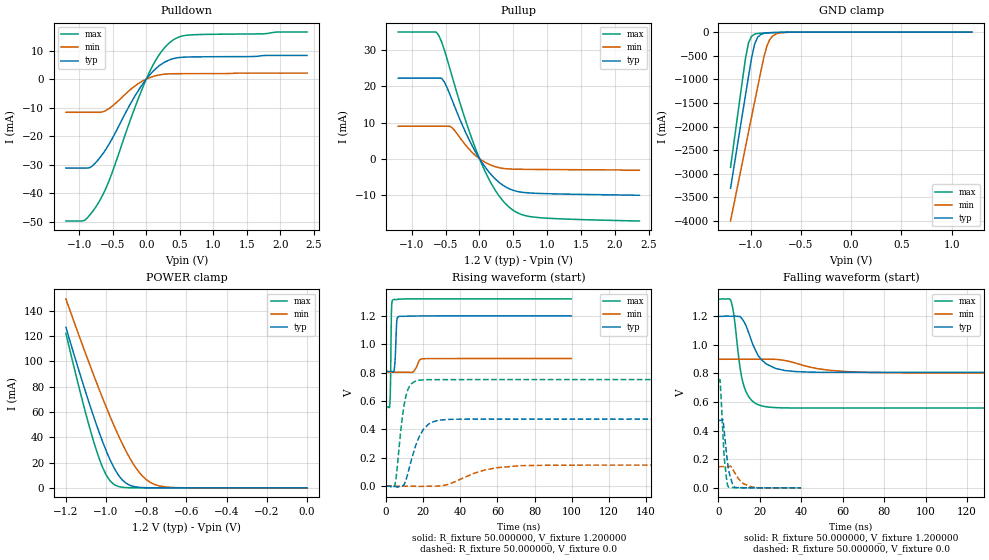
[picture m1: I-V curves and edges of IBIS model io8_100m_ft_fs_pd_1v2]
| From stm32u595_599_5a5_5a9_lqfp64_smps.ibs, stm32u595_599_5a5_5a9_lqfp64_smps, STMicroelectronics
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|   Model io8_100m_ft_fs_pd_1v2
[Model]  io8_100m_ft_fs_pd_1v2
Model_type I/O
Polarity   Non-Inverting
Enable   Active-Low
Vinl =   0.360000V
Vinh =   0.840000V
Vmeas =  0.600000V
Cref =   50.000000pF
Rref =   100.000000M
Vref =   0.0V
C_comp   2.947800pF   2.877700pF   2.996100pF
[Temperature Range]   25.000000   0.140000k   -40.000000
[Pullup Reference]   1.200000V   0.900000V   1.320000V
[Pulldown Reference]   0.0V   0.0V   0.0V
[POWER Clamp Reference]   1.200000V   0.900000V   1.320000V
[GND Clamp Reference]   0.0V   0.0V   0.0V
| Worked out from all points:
|   slope of the pulldown table from 0 to 0.18 V, typ, clamps not added: 40.7 ohm
|   slope of the pullup table from 0 to 0.18 V, typ, clamps not added: 39.5 ohm
|   GND clamp passes 1 mA (typ) near -0.51 V on its own axis
|   POWER clamp passes 1 mA (typ) near -0.86 V on its own axis
|   rising waveform, R_fixture 50.000000, V_fixture 1.200000: 20-80 % time 754ps typ, 2.06ns min, 443ps max; typ from 0.808 V to 1.2 V
|   rising waveform, R_fixture 50.000000, V_fixture 0.0: 20-80 % time 7.28ns typ, 18.3ns min, 3.99ns max; typ from 0 V to 0.472 V
|   falling waveform, R_fixture 50.000000, V_fixture 1.200000: 20-80 % time 7.88ns typ, 18.5ns min, 4.53ns max; typ from 1.2 V to 0.808 V
|   falling waveform, R_fixture 50.000000, V_fixture 0.0: 20-80 % time 2.49ns typ, 4.75ns min, 1.85ns max; typ from 0.472 V to 0 V
[Pulldown]
|Voltage   I(typ)   I(min)   I(max)
-1.2V     -31.16mA   -11.61mA   -49.71mA
-920mV    -31.16mA   -11.61mA   -49.48mA
-840mV    -31mA      -11.61mA   -47.54mA
-720mV    -28.33mA   -11.61mA   -43.58mA
-560mV    -22.95mA   -10.37mA   -35.89mA
-200mV    -7.146mA   -2.964mA   -11.89mA
0V        0A         0A         0A
160mV     4.047mA    1.298mA    7.361mA
360mV     6.87mA     1.87mA     13mA
480mV     7.543mA    1.91mA     14.69mA
640mV     7.765mA    1.923mA    15.46mA
2.4V      8.308mA    2.101mA    16.51mA
[Pullup]
|Voltage   I(typ)   I(min)   I(max)
-1.2V     22.25mA    8.971mA    35.01mA
-640mV    22.25mA    8.971mA    35.01mA
-600mV    22.25mA    8.971mA    34.03mA
-520mV    21.23mA    8.971mA    30.12mA
-400mV    15.99mA    8.489mA    22.45mA
-200mV    7.069mA    3.642mA    10.26mA
0V        0A         0A         0A
240mV     -5.73mA    -2.256mA   -8.953mA
480mV     -8.639mA   -2.877mA   -14.04mA
640mV     -9.31mA    -2.942mA   -15.55mA
880mV     -9.601mA   -2.986mA   -16.29mA
2.36V     -10.1mA    -3.2mA     -17.23mA
[GND_clamp]
|Voltage   I(typ)   I(min)   I(max)
-1.2V     -3.305A    -3.998A    -2.862A
-1.05V    -1.316A    -2.418A    -539.3mA
-1.02V    -921mA     -2.103A    -218.8mA
-990mV    -539.5mA   -1.788A    -87.45mA
-960mV    -252.2mA   -1.474A    -44.37mA
-930mV    -110.5mA   -1.16A     -30.33mA
-870mV    -28.04mA   -549.1mA   -21.1mA
-840mV    -18.44mA   -305.6mA   -18.29mA
-810mV    -13.92mA   -159.7mA   -15.75mA
-780mV    -11.24mA   -82.36mA   -13.39mA
-600mV    -2.986mA   -4.279mA   -3.072mA
1.2V      30.28uA    18.17uA    37.27uA
[POWER_clamp]
|Voltage   I(typ)   I(min)   I(max)
-1.2V     127mA      149.4mA    122.2mA
-1.12V    84.97mA    114mA      70.27mA
-1.06V    55.51mA    88.42mA    35.67mA
-1.02V    37.63mA    72.04mA    17.17mA
-1V       29.51mA    64.13mA    10.3mA
-960mV    15.69mA    48.99mA    2.571mA
-900mV    3.624mA    28.77mA    182.8uA
-840mV    490.7uA    13.24mA    11.35uA
-800mV    116.8uA    6.532mA    1.77uA
-740mV    13.2uA     1.723mA    109.1nA
-620mV    167.3nA    79.35uA    0A
0V        0A         17.84nA    0A
[Ramp]
| variable   typ   min   max
dV/dt_r  0.28341/7.27297n   88.82988m/18.29477n 0.45044/3.98024n
dV/dt_f  0.23482/7.86802n   58.05000m/18.47771n 0.45673/4.52218n
R_load = 50.000000
[Rising Waveform]
R_fixture= 50.000000
V_fixture= 1.200000
V_fixture_min= 0.900000
V_fixture_max= 1.320000
|time   V(typ)   V(min)   V(max)
0s        808mV      802.7mV    558.2mV
2.002ns   808mV      802.7mV    574.3mV
2.402ns   808.1mV    802.7mV    765.3mV
2.803ns   807.9mV    802.7mV    1.21V
3.804ns   803.9mV    802.7mV    1.313V
4.605ns   851.3mV    802.7mV    1.315V
5.806ns   1.172V     802.7mV    1.316V
6.807ns   1.195V     802.7mV    1.317V
19.62ns   1.199V     897.2mV    1.319V
99.7ns    1.199V     899.4mV    1.319V
[Rising Waveform]
R_fixture= 50.000000
V_fixture= 0.0
V_fixture_min= 0.0
V_fixture_max= 0.0
|time   V(typ)   V(min)   V(max)
0s        1.836uV    1.079uV    1.945uV
4.805ns   -2.478mV   908.2nV    12.66mV
8.408ns   -277.8uV   -126.5nV   450.6mV
10.21ns   26.56mV    1.789uV    609.2mV
12.61ns   135.9mV    47.98uV    703.9mV
17.42ns   336.6mV    -1.605mV   745.1mV
22.82ns   436mV      -111.7uV   750.3mV
34.23ns   470.2mV    16.31mV    750.6mV
72.67ns   472.3mV    144.2mV    750.7mV
299.1ns   472.4mV    148.1mV    750.7mV
[Falling Waveform]
R_fixture= 50.000000
V_fixture= 1.200000
V_fixture_min= 0.900000
V_fixture_max= 1.320000
|time   V(typ)   V(min)   V(max)
0s        1.199V     899.4mV    1.319V
6.006ns   1.2V       899.5mV    1.309V
7.608ns   1.201V     900mV      1.189V
10.41ns   1.198V     900mV      841mV
12.01ns   1.169V     899.8mV    725.5mV
15.62ns   1.043V     899.6mV    618.5mV
20.82ns   895.3mV    899.6mV    573.7mV
38.04ns   812.6mV    869.1mV    558.4mV
72.47ns   807.9mV    807.3mV    558.2mV
199.4ns   808mV      802.7mV    558.2mV
[Falling Waveform]
R_fixture= 50.000000
V_fixture= 0.0
V_fixture_min= 0.0
V_fixture_max= 0.0
|time   V(typ)   V(min)   V(max)
0s        472.4mV    148.1mV    750.7mV
800.8ps   472.4mV    148.1mV    742.4mV
2.162ns   472.9mV    148.1mV    370mV
3.043ns   356.7mV    148.1mV    172.2mV
4.084ns   213.5mV    147.9mV    42.43mV
4.725ns   141.8mV    148.4mV    7.59mV
7.928ns   3.644mV    103.3mV    955.4uV
11.61ns   1.053mV    33.9mV     280.4uV
17.38ns   292.5uV    2.83mV     68.81uV
39.88ns   1.836uV    1.079uV    1.945uV
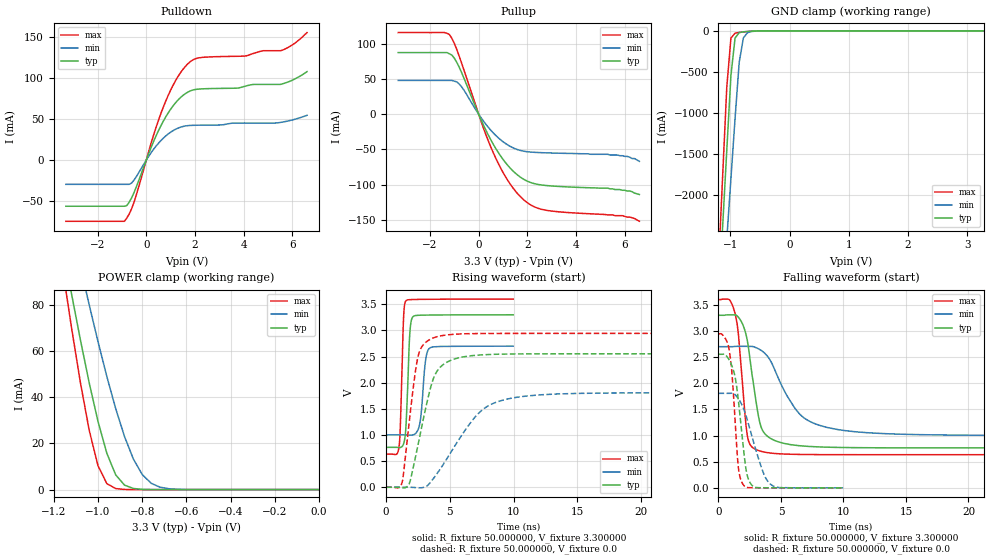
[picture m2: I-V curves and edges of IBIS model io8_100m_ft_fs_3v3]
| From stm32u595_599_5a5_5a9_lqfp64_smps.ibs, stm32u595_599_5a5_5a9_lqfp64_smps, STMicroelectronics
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|   Model io8_100m_ft_fs_3v3
[Model]  io8_100m_ft_fs_3v3
Model_type I/O
Polarity   Non-Inverting
Enable   Active-Low
Vinl =   0.990000V
Vinh =   2.310000V
Vmeas =  1.650000V
Cref =   50.000000pF
Rref =   100.000000M
Vref =   0.0V
C_comp   3.313100pF   3.281800pF   3.354500pF
[Temperature Range]   25.000000   0.140000k   -40.000000
[Pullup Reference]   3.300000V   2.700000V   3.600000V
[Pulldown Reference]   0.0V   0.0V   0.0V
[POWER Clamp Reference]   3.300000V   2.700000V   3.600000V
[GND Clamp Reference]   0.0V   0.0V   0.0V
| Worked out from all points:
|   slope of the pulldown table from 0 to 0.495 V, typ, clamps not added: 14 ohm
|   slope of the pullup table from 0 to 0.495 V, typ, clamps not added: 13.7 ohm
|   GND clamp passes 1 mA (typ) near -0.51 V on its own axis
|   POWER clamp passes 1 mA (typ) near -0.85 V on its own axis
|   rising waveform, R_fixture 50.000000, V_fixture 3.300000: 20-80 % time 245ps typ, 343ps min, 208ps max; typ from 0.764 V to 3.3 V
|   rising waveform, R_fixture 50.000000, V_fixture 0.0: 20-80 % time 1.41ns typ, 3.11ns min, 873ps max; typ from 0 V to 2.55 V
|   falling waveform, R_fixture 50.000000, V_fixture 3.300000: 20-80 % time 962ps typ, 2.52ns min, 631ps max; typ from 3.3 V to 0.764 V
|   falling waveform, R_fixture 50.000000, V_fixture 0.0: 20-80 % time 727ps typ, 1.36ns min, 504ps max; typ from 2.55 V to 0 V
[Pulldown]
|Voltage   I(typ)   I(min)   I(max)
-3.3V     -56.06mA   -29.42mA   -74.35mA
-900mV    -56.06mA   -29.42mA   -74.35mA
-700mV    -51.09mA   -29.42mA   -65.48mA
-500mV    -39.32mA   -24.2mA    -50.88mA
300mV     22.62mA    13.13mA    30.43mA
800mV     52.54mA    29.36mA    71.75mA
1.3V      72.91mA    38.82mA    101.4mA
1.8V      84.02mA    42.13mA    119.4mA
2.2V      86.43mA    42.46mA    124.5mA
5.5V      91.98mA    45.75mA    132.9mA
6.1V      98.6mA     49.6mA     142.1mA
6.6V      107.5mA    54.5mA     155mA
[Pullup]
|Voltage   I(typ)   I(min)   I(max)
-3.3V     87.21mA    47.72mA    115.6mA
-1.2V     85.52mA    47.72mA    112.9mA
-1V       79.41mA    46.66mA    100.4mA
-700mV    59.08mA    38.76mA    72.42mA
100mV     -8.009mA   -5.102mA   -10.2mA
600mV     -42.64mA   -26.6mA    -54.61mA
1.2V      -72.81mA   -43.84mA   -94.18mA
1.9V      -93.37mA   -52.9mA    -122.9mA
2.3V      -98.71mA   -54.23mA   -131.6mA
2.8V      -101.3mA   -54.97mA   -136.5mA
5.7V      -107mA     -58mA      -144mA
6.6V      -114mA     -67mA      -152mA
[GND_clamp]
|Voltage   I(typ)   I(min)   I(max)
-3.3V     -9.848A    -9.957A    -9.458A
-1.2V     -3.312A    -4.013A    -2.863A
-1.13V    -2.381A    -3.274A    -1.769A
-1.06V    -1.452A    -2.535A    -684.7mA
-990mV    -542.9mA   -1.798A    -88.02mA
-920mV    -87.11mA   -1.064A    -28.44mA
-850mV    -22.1mA    -382.4mA   -19.61mA
-780mV    -11.97mA   -86.98mA   -13.71mA
-710mV    -7.619mA   -22.26mA   -8.745mA
-640mV    -4.493mA   -7.773mA   -4.817mA
-360mV    -31.22uA   -172.6uA   -8.607uA
3.28V     0A         15.66nA    -5.841nA
[POWER_clamp]
|Voltage   I(typ)   I(min)   I(max)
-3.28V    1.355A     1.167A     1.664A
-1.16V    105.7mA    131.6mA    95.69mA
-1.12V    84.97mA    114mA      70.27mA
-1.08V    65.05mA    96.83mA    46.54mA
-1.04V    46.34mA    80.15mA    25.76mA
-1V       29.51mA    64.13mA    10.3mA
-960mV    15.69mA    48.99mA    2.571mA
-920mV    6.373mA    35.1mA     455.6uA
-840mV    490.7uA    13.24mA    11.36uA
-760mV    27.33uA    2.767mA    276.6nA
-640mV    346.6nA    134.1uA    15.62nA
0V        0A         19.91nA    0A
[Ramp]
| variable   typ   min   max
dV/dt_r  1.53252/1.41111n   1.08438/3.10153n   1.76664/0.87123n
dV/dt_f  1.52149/0.95835n   1.01892/2.51269n   1.77964/0.62530n
R_load = 50.000000
[Rising Waveform]
R_fixture= 50.000000
V_fixture= 3.300000
V_fixture_min= 2.700000
V_fixture_max= 3.600000
|time   V(typ)   V(min)   V(max)
0s        764.2mV    1.002V     633.9mV
1.021ns   760mV      1.002V     794mV
1.361ns   826.9mV    1.002V     3.216V
1.542ns   1.121V     1.002V     3.565V
1.842ns   2.884V     999.4mV    3.59V
2.102ns   3.263V     1.002V     3.592V
2.623ns   3.292V     1.198V     3.595V
3.083ns   3.294V     2.409V     3.596V
3.423ns   3.295V     2.664V     3.597V
9.97ns    3.3V       2.7V       3.6V
[Rising Waveform]
R_fixture= 50.000000
V_fixture= 0.0
V_fixture_min= 0.0
V_fixture_max= 0.0
|time   V(typ)   V(min)   V(max)
0s        8.008uV    7.157uV    6.555uV
1.201ns   -7.026mV   12.94uV    54.62mV
1.802ns   59.79mV    -885.5nV   1.225V
2.302ns   579.4mV    -6.089mV   2.227V
2.603ns   930.2mV    -10.13mV   2.59V
3.504ns   1.921V     103.9mV    2.836V
4.204ns   2.287V     335.2mV    2.893V
7.407ns   2.532V     1.452V     2.942V
10.51ns   2.551V     1.731V     2.944V
49.85ns   2.554V     1.807V     2.944V
[Falling Waveform]
R_fixture= 50.000000
V_fixture= 3.300000
V_fixture_min= 2.700000
V_fixture_max= 3.600000
|time   V(typ)   V(min)   V(max)
0s        3.3V       2.7V       3.6V
1.301ns   3.307V     2.704V     3.356V
1.602ns   3.26V      2.706V     2.919V
2.002ns   3.088V     2.706V     1.743V
2.402ns   2.676V     2.706V     898.8mV
3.103ns   1.5V       2.67V      722.6mV
3.504ns   1.108V     2.614V     693.1mV
6.507ns   805.4mV    1.408V     639.2mV
9.61ns    773.2mV    1.112V     634.7mV
49.85ns   764.2mV    1.002V     633.9mV
[Falling Waveform]
R_fixture= 50.000000
V_fixture= 0.0
V_fixture_min= 0.0
V_fixture_max= 0.0
|time   V(typ)   V(min)   V(max)
0s        2.554V     1.807V     2.944V
860.9ps   2.444V     1.807V     2.631V
1.101ns   2.315V     1.811V     2.115V
1.582ns   1.687V     1.707V     408.2mV
2.022ns   699.6mV    1.505V     46.54mV
2.282ns   257.8mV    1.317V     7.734mV
2.583ns   75.88mV    1.064V     3.106mV
3.564ns   2.516mV    303mV      1.396mV
4.184ns   1.63mV     64.39mV    1.075mV
9.97ns    8.008uV    7.157uV    6.555uV
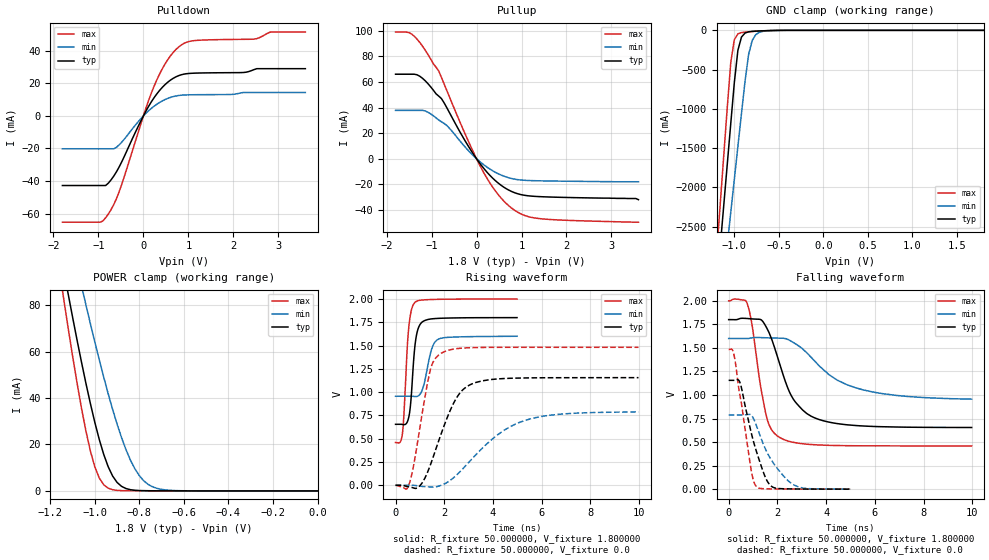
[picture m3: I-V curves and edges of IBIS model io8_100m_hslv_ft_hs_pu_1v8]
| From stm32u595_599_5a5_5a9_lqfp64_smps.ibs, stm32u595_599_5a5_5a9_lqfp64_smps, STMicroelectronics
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|   Model io8_100m_hslv_ft_hs_pu_1v8
[Model]  io8_100m_hslv_ft_hs_pu_1v8
Model_type I/O
Polarity   Non-Inverting
Enable   Active-Low
Vinl =   0.540000V
Vinh =   1.260000V
Vmeas =  0.900000V
Cref =   50.000000pF
Rref =   100.000000M
Vref =   0.0V
C_comp   3.235100pF   3.233200pF   3.282800pF
[Temperature Range]   25.000000   0.140000k   -40.000000
[Pullup Reference]   1.800000V   1.600000V   2.000000V
[Pulldown Reference]   0.0V   0.0V   0.0V
[POWER Clamp Reference]   1.800000V   1.600000V   2.000000V
[GND Clamp Reference]   0.0V   0.0V   0.0V
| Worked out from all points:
|   slope of the pulldown table from 0 to 0.27 V, typ, clamps not added: 21.7 ohm
|   slope of the pullup table from 0 to 0.27 V, typ, clamps not added: 22.6 ohm
|   GND clamp passes 1 mA (typ) near -0.51 V on its own axis
|   POWER clamp passes 1 mA (typ) near -0.86 V on its own axis
|   rising waveform, R_fixture 50.000000, V_fixture 1.800000: 20-80 % time 211ps typ, 326ps min, 197ps max; typ from 0.655 V to 1.8 V
|   rising waveform, R_fixture 50.000000, V_fixture 0.0: 20-80 % time 1.02ns typ, 2.03ns min, 582ps max; typ from 0.001 V to 1.16 V
|   falling waveform, R_fixture 50.000000, V_fixture 1.800000: 20-80 % time 1.08ns typ, 2.01ns min, 566ps max; typ from 1.8 V to 0.655 V
|   falling waveform, R_fixture 50.000000, V_fixture 0.0: 20-80 % time 711ps typ, 991ps min, 511ps max; typ from 1.16 V to 0.001 V
[Pulldown]
|Voltage   I(typ)   I(min)   I(max)
-1.8V     -42.74mA   -20.21mA   -65.25mA
-960mV    -42.74mA   -20.21mA   -65.25mA
-780mV    -41.3mA    -20.21mA   -60.25mA
-540mV    -31.39mA   -17.82mA   -46.65mA
0V        0A         0A         0A
240mV     11.28mA    6.002mA    18.38mA
480mV     19.17mA    10.02mA    31.83mA
780mV     24.67mA    12.5mA     42.21mA
1.14V     26.24mA    12.99mA    46.23mA
2.46V     28.42mA    14.38mA    47.14mA
2.82V     28.99mA    14.38mA    51.44mA
3.6V      28.99mA    14.38mA    51.44mA
[Pullup]
|Voltage   I(typ)   I(min)   I(max)
-1.8V     66.02mA    37.77mA    98.94mA
-1.44V    66.02mA    37.77mA    97.34mA
-1.14V    60.88mA    37.29mA    84.8mA
-840mV    48.91mA    30.23mA    68.54mA
-660mV    39.82mA    25.94mA    53.25mA
-300mV    16.72mA    11mA       23.08mA
120mV     -5.748mA   -3.603mA   -8.316mA
420mV     -17.18mA   -10.64mA   -25.23mA
780mV     -25.61mA   -15.48mA   -38.6mA
1.08V     -28.66mA   -16.9mA    -44.47mA
1.38V     -29.58mA   -17.26mA   -46.72mA
3.6V      -32mA      -18mA      -49.6mA
[GND_clamp]
|Voltage   I(typ)   I(min)   I(max)
-1.8V     -9.707A    -9.942A    -9.774A
-1.2V     -3.309A    -4.006A    -2.864A
-1.16V    -2.777A    -3.584A    -2.239A
-1.12V    -2.246A    -3.162A    -1.614A
-1.04V    -1.186A    -2.319A    -408.6mA
-1V       -663.9mA   -1.898A    -117.8mA
-960mV    -254mA     -1.478A    -45.14mA
-920mV    -86.03mA   -1.06A     -28.58mA
-840mV    -19.12mA   -308.9mA   -18.74mA
-800mV    -13.39mA   -130.8mA   -15.31mA
-720mV    -7.948mA   -25.37mA   -9.381mA
1.8V      0A         14.95nA    0A
[POWER_clamp]
|Voltage   I(typ)   I(min)   I(max)
-1.8V     470.9mA    433.7mA    554.6mA
-1.14V    95.28mA    122.7mA    82.88mA
-1.12V    85mA       114mA      70.34mA
-1.06V    55.55mA    88.43mA    35.73mA
-1.04V    46.38mA    80.17mA    25.83mA
-1V       29.54mA    64.14mA    10.37mA
-940mV    10.43mA    41.88mA    1.177mA
-900mV    3.66mA     28.79mA    250.5uA
-840mV    527.2uA    13.26mA    94.87uA
-800mV    153.8uA    6.55mA     88.76uA
-740mV    60.08uA    1.741mA    70.81uA
0V        0A         18.15nA    0A
[Ramp]
| variable   typ   min   max
dV/dt_r  0.69287/1.02352n   0.47044/2.02009n   0.88849/0.58120n
dV/dt_f  0.68675/1.08263n   0.37898/1.99355n   0.92438/0.56597n
R_load = 50.000000
[Rising Waveform]
R_fixture= 50.000000
V_fixture= 1.800000
V_fixture_min= 1.600000
V_fixture_max= 2.000000
|time   V(typ)   V(min)   V(max)
0s        655mV      956.1mV    459.6mV
200.2ps   655.2mV    956.2mV    468.1mV
290.3ps   653.6mV    956.3mV    573.3mV
520.5ps   708.7mV    956.7mV    1.632V
620.6ps   881.1mV    956.6mV    1.843V
780.8ps   1.46V      953.9mV    1.959V
1.031ns   1.736V     988.3mV    1.987V
1.481ns   1.787V     1.462V     1.995V
1.752ns   1.792V     1.568V     1.996V
4.985ns   1.8V       1.6V       1.999V
[Rising Waveform]
R_fixture= 50.000000
V_fixture= 0.0
V_fixture_min= 0.0
V_fixture_max= 0.0
|time   V(typ)   V(min)   V(max)
0s        502.3uV    658.3uV    580.3uV
560.6ps   -17.27mV   654uV      15.83mV
1.001ns   -3.887mV   -9.049mV   622.6mV
1.421ns   213.2mV    -17.61mV   1.232V
1.882ns   560.3mV    1.428mV    1.419V
2.563ns   962.7mV    124.8mV    1.468V
3.303ns   1.105V     330.2mV    1.479V
4.424ns   1.146V     585.6mV    1.481V
5.626ns   1.154V     719.8mV    1.482V
9.97ns    1.156V     787.5mV    1.482V
[Falling Waveform]
R_fixture= 50.000000
V_fixture= 1.800000
V_fixture_min= 1.600000
V_fixture_max= 2.000000
|time   V(typ)   V(min)   V(max)
0s        1.8V       1.6V       1.999V
740.7ps   1.812V     1.599V     1.984V
920.9ps   1.808V     1.605V     1.802V
1.301ns   1.802V     1.609V     1.106V
1.542ns   1.721V     1.607V     783.5mV
2.082ns   1.34V      1.603V     550.7mV
2.683ns   944.8mV    1.552V     496.1mV
3.704ns   740.3mV    1.313V     469.5mV
5.786ns   667.7mV    1.039V     460.5mV
9.97ns    655mV      956.1mV    459.6mV
[Falling Waveform]
R_fixture= 50.000000
V_fixture= 0.0
V_fixture_min= 0.0
V_fixture_max= 0.0
|time   V(typ)   V(min)   V(max)
0s        1.156V     787.5mV    1.482V
210.2ps   1.156V     787.6mV    1.434V
450.5ps   1.14V      787.7mV    1.012V
940.9ps   583.8mV    781.8mV    177.3mV
1.141ns   399.4mV    673.4mV    26.79mV
1.481ns   141.5mV    442.7mV    4.929mV
1.682ns   48.67mV    339.8mV    3.591mV
2.563ns   3.225mV    64.23mV    1.463mV
3.063ns   1.947mV    11.46mV    1.045mV
4.985ns   502.3uV    658.3uV    580.3uV
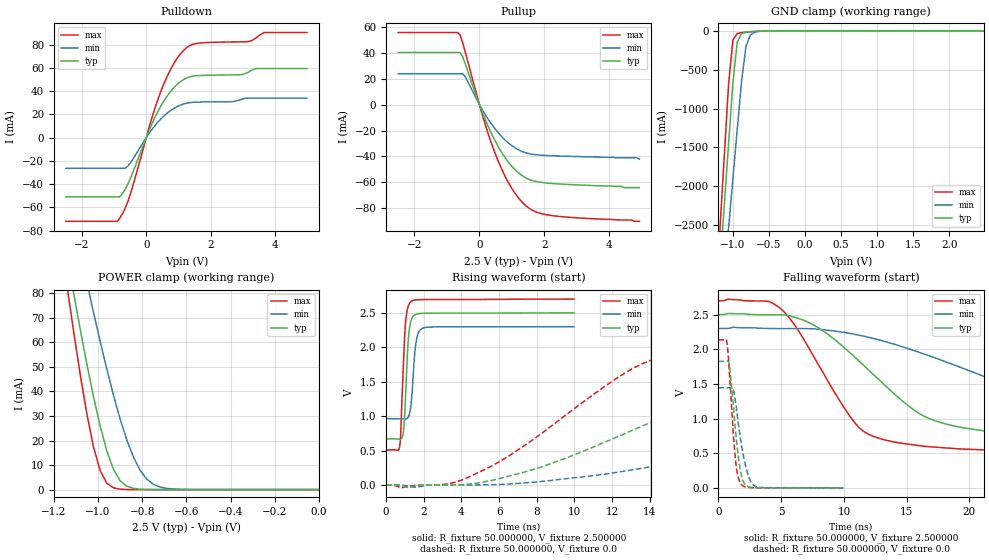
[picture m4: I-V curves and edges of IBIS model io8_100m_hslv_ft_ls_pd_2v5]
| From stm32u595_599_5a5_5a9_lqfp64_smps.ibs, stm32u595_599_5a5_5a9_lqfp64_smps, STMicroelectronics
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|   Model io8_100m_hslv_ft_ls_pd_2v5
[Model]  io8_100m_hslv_ft_ls_pd_2v5
Model_type I/O
Polarity   Non-Inverting
Enable   Active-Low
Vinl =   0.750000V
Vinh =   1.750000V
Vmeas =  1.250000V
Cref =   50.000000pF
Rref =   100.000000M
Vref =   0.0V
C_comp   3.340800pF   3.338500pF   3.380300pF
[Temperature Range]   25.000000   0.140000k   -40.000000
[Pullup Reference]   2.500000V   2.300000V   2.700000V
[Pulldown Reference]   0.0V   0.0V   0.0V
[POWER Clamp Reference]   2.500000V   2.300000V   2.700000V
[GND Clamp Reference]   0.0V   0.0V   0.0V
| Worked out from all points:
|   slope of the pulldown table from 0 to 0.375 V, typ, clamps not added: 16.1 ohm
|   slope of the pullup table from 0 to 0.375 V, typ, clamps not added: 16.6 ohm
|   GND clamp passes 1 mA (typ) near -0.50 V on its own axis
|   POWER clamp passes 1 mA (typ) near -0.86 V on its own axis
|   rising waveform, R_fixture 50.000000, V_fixture 2.500000: 20-80 % time 198ps typ, 224ps min, 202ps max; typ from 0.67 V to 2.5 V
|   rising waveform, R_fixture 50.000000, V_fixture 0.0: 20-80 % time 9.99ns typ, 18.1ns min, 6.67ns max; typ from 0 V to 1.82 V
|   falling waveform, R_fixture 50.000000, V_fixture 2.500000: 20-80 % time 7.08ns typ, 14.2ns min, 4.43ns max; typ from 2.5 V to 0.67 V
|   falling waveform, R_fixture 50.000000, V_fixture 0.0: 20-80 % time 598ps typ, 782ps min, 495ps max; typ from 1.82 V to 0 V
[Pulldown]
|Voltage   I(typ)   I(min)   I(max)
-2.5V     -51.01mA   -26.45mA   -72.04mA
-900mV    -51.01mA   -26.45mA   -72.04mA
-820mV    -50.89mA   -26.45mA   -69.09mA
-500mV    -35.59mA   -21.93mA   -49.09mA
140mV     9.489mA    5.639mA    13.76mA
460mV     27.5mA     16.24mA    40.22mA
860mV     43.07mA    25.18mA    63.88mA
1.26V     51.38mA    29.65mA    77.49mA
1.66V     53.45mA    30.63mA    81.42mA
3.18V     56.44mA    34.01mA    82.68mA
3.66V     59.44mA    34.01mA    90.42mA
5V        59.44mA    34.01mA    90.42mA
[Pullup]
|Voltage   I(typ)   I(min)   I(max)
-2.5V     40.22mA    23.82mA    55.53mA
-680mV    40.22mA    23.82mA    55.53mA
-600mV    40.22mA    23.82mA    53.98mA
-440mV    31.7mA     21.6mA     40.82mA
120mV     -7.857mA   -5.279mA   -10.51mA
520mV     -29.75mA   -19.94mA   -40.02mA
760mV     -39.83mA   -26.61mA   -53.83mA
1V        -47.69mA   -31.74mA   -64.85mA
1.48V     -57.16mA   -37.55mA   -79.04mA
1.8V      -59.59mA   -38.81mA   -83.34mA
2.28V     -60.92mA   -39.5mA    -85.75mA
4.92V     -64mA      -42mA      -90mA
[GND_clamp]
|Voltage   I(typ)   I(min)   I(max)
-2.5V     -9.446A    -9.524A    -9.146A
-1.18V    -3.045A    -3.8A      -2.552A
-1.12V    -2.248A    -3.166A    -1.614A
-1.06V    -1.452A    -2.533A    -685.4mA
-1V       -665mA     -1.901A    -117.9mA
-940mV    -148mA     -1.272A    -34.34mA
-880mV    -35.14mA   -651.5mA   -22.8mA
-820mV    -16.02mA   -203.9mA   -17.08mA
-760mV    -10.47mA   -56.89mA   -12.28mA
-700mV    -7.079mA   -18.53mA   -8.16mA
-400mV    -112.4uA   -382.5uA   -53.84uA
2.48V     63.1uA     48.03uA    77.39uA
[POWER_clamp]
|Voltage   I(typ)   I(min)   I(max)
-2.49V    881mA      773.1mA    1.07A
-1.14V    95.25mA    122.7mA    82.82mA
-1.11V    79.9mA     109.7mA    64.14mA
-1.05V    50.87mA    84.26mA    30.57mA
-1.02V    37.63mA    72.04mA    17.17mA
-990mV    25.71mA    60.25mA    7.621mA
-930mV    8.217mA    38.43mA    713.9uA
-900mV    3.624mA    28.77mA    182.8uA
-840mV    490.7uA    13.24mA    11.35uA
-780mV    56.55uA    4.324mA    699nA
-660mV    716.5nA    226uA      9.775nA
0V        0A         19.49nA    0A
[Ramp]
| variable   typ   min   max
dV/dt_r  1.09464/9.98017n   0.86544/18.06439n   1.28148/6.66219n
dV/dt_f  1.09787/7.06791n   0.80199/14.15454n   1.31323/4.42247n
R_load = 50.000000
[Rising Waveform]
R_fixture= 50.000000
V_fixture= 2.500000
V_fixture_min= 2.300000
V_fixture_max= 2.700000
|time   V(typ)   V(min)   V(max)
0s        669.5mV    962.5mV    510.5mV
720.7ps   665.8mV    962.5mV    563.1mV
780.8ps   667.4mV    962.4mV    792.1mV
920.9ps   780.8mV    961.4mV    1.768V
1.021ns   1.226V     958.8mV    2.324V
1.161ns   2.048V     980.5mV    2.586V
1.321ns   2.383V     1.168V     2.664V
1.582ns   2.477V     2.059V     2.688V
1.922ns   2.492V     2.275V     2.693V
9.97ns    2.499V     2.299V     2.699V
[Rising Waveform]
R_fixture= 50.000000
V_fixture= 0.0
V_fixture_min= 0.0
V_fixture_max= 0.0
|time   V(typ)   V(min)   V(max)
0s        2.474nV    121.9nV    2.503nV
2.803ns   -1.325mV   -1.105mV   2.414mV
4.404ns   13.92mV    35.28uV    117.6mV
8.008ns   241.7mV    44.82mV    699.7mV
14.01ns   904mV      262.5mV    1.805V
18.82ns   1.423V     502.2mV    2.033V
21.62ns   1.594V     649.8mV    2.081V
33.63ns   1.787V     1.183V     2.131V
50.45ns   1.821V     1.389V     2.136V
199.4ns   1.825V     1.442V     2.136V
[Falling Waveform]
R_fixture= 50.000000
V_fixture= 2.500000
V_fixture_min= 2.300000
V_fixture_max= 2.700000
|time   V(typ)   V(min)   V(max)
0s        2.499V     2.299V     2.699V
4.004ns   2.497V     2.299V     2.69V
5.205ns   2.496V     2.298V     2.544V
8.008ns   2.304V     2.287V     1.762V
11.61ns   1.759V     2.187V     809.5mV
16.02ns   1.071V     1.954V     608.4mV
19.22ns   876.7mV    1.743V     561.7mV
29.63ns   721.9mV    1.21V      520mV
49.25ns   676.3mV    1.018V     511mV
199.4ns   669.5mV    962.5mV    510.5mV
[Falling Waveform]
R_fixture= 50.000000
V_fixture= 0.0
V_fixture_min= 0.0
V_fixture_max= 0.0
|time   V(typ)   V(min)   V(max)
0s        1.825V     1.442V     2.136V
620.6ps   1.824V     1.443V     2.138V
840.8ps   1.796V     1.443V     1.729V
1.141ns   1.276V     1.438V     887.5mV
1.361ns   815.7mV    1.229V     394.3mV
1.562ns   476.7mV    954.7mV    160.7mV
1.822ns   179.9mV    628.8mV    51.24mV
2.362ns   18.82mV    184.6mV    6.293mV
2.943ns   2.456mV    21.58mV    1.465mV
9.97ns    2.474nV    121.9nV    2.503nV
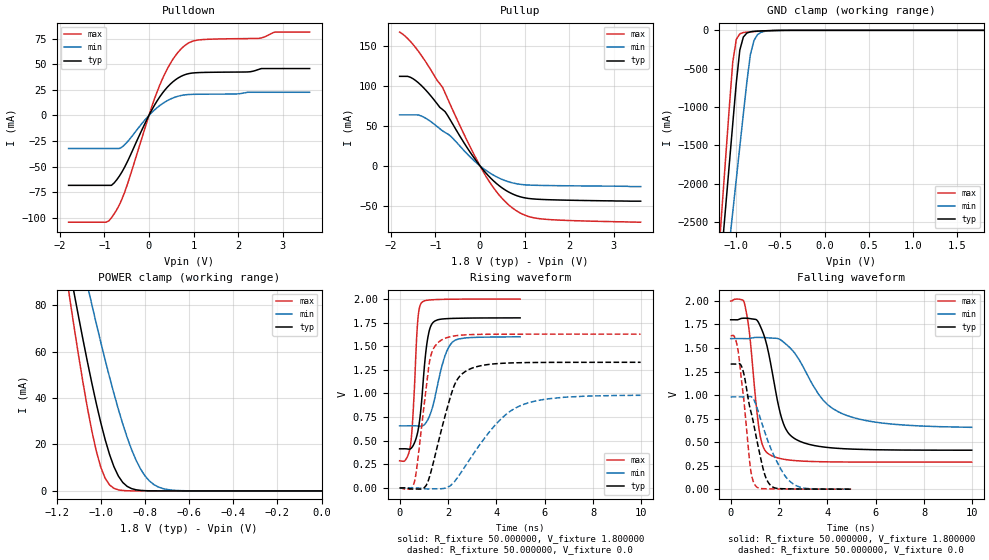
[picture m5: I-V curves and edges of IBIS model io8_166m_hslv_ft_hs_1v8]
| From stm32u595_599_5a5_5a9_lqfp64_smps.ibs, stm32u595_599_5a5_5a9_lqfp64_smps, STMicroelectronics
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|   Model io8_166m_hslv_ft_hs_1v8
[Model]  io8_166m_hslv_ft_hs_1v8
Model_type I/O
Polarity   Non-Inverting
Enable   Active-Low
Vinl =   0.540000V
Vinh =   1.260000V
Vmeas =  0.900000V
Cref =   50.000000pF
Rref =   100.000000M
Vref =   0.0V
C_comp   3.358400pF   3.352800pF   3.400400pF
[Temperature Range]   25.000000   0.140000k   -40.000000
[Pullup Reference]   1.800000V   1.600000V   2.000000V
[Pulldown Reference]   0.0V   0.0V   0.0V
[POWER Clamp Reference]   1.800000V   1.600000V   2.000000V
[GND Clamp Reference]   0.0V   0.0V   0.0V
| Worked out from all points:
|   slope of the pulldown table from 0 to 0.27 V, typ, clamps not added: 13.6 ohm
|   slope of the pullup table from 0 to 0.27 V, typ, clamps not added: 15.9 ohm
|   GND clamp passes 1 mA (typ) near -0.51 V on its own axis
|   POWER clamp passes 1 mA (typ) near -0.86 V on its own axis
|   rising waveform, R_fixture 50.000000, V_fixture 1.800000: 20-80 % time 311ps typ, 546ps min, 203ps max; typ from 0.414 V to 1.8 V
|   rising waveform, R_fixture 50.000000, V_fixture 0.0: 20-80 % time 838ps typ, 1.81ns min, 451ps max; typ from 0 V to 1.33 V
|   falling waveform, R_fixture 50.000000, V_fixture 1.800000: 20-80 % time 688ps typ, 1.56ns min, 401ps max; typ from 1.8 V to 0.414 V
|   falling waveform, R_fixture 50.000000, V_fixture 0.0: 20-80 % time 636ps typ, 926ps min, 386ps max; typ from 1.33 V to 0 V
[Pulldown]
|Voltage   I(typ)   I(min)   I(max)
-1.8V     -68.38mA   -32.32mA   -104.4mA
-960mV    -68.38mA   -32.32mA   -104.4mA
-780mV    -66.08mA   -32.32mA   -96.42mA
-540mV    -50.22mA   -28.51mA   -74.66mA
0V        0A         -400fA     10fA
240mV     18.04mA    9.6mA      29.42mA
480mV     30.68mA    16.02mA    50.95mA
780mV     39.48mA    19.99mA    67.57mA
1.14V     41.99mA    20.78mA    74.01mA
2.46V     45.09mA    22.69mA    75.45mA
2.82V     45.91mA    22.69mA    81.58mA
3.6V      45.91mA    22.69mA    81.58mA
[Pullup]
|Voltage   I(typ)   I(min)   I(max)
-1.8V     111.9mA    63.74mA    167.2mA
-1.56V    110.8mA    63.74mA    155.7mA
-1.26V    97.43mA    60.93mA    133.8mA
-840mV    70.5mA     43.75mA    98.31mA
-660mV    56.92mA    37.26mA    75.93mA
-300mV    23.77mA    15.64mA    32.82mA
120mV     -8.174mA   -5.123mA   -11.83mA
420mV     -24.43mA   -15.12mA   -35.87mA
720mV     -34.96mA   -21.23mA   -52.43mA
1.02V     -40.21mA   -23.8mA    -62.05mA
1.38V     -42.05mA   -24.52mA   -66.41mA
3.6V      -44.2mA    -26mA      -70.5mA
[GND_clamp]
|Voltage   I(typ)   I(min)   I(max)
-1.8V     -9.908A    -9.683A    -9.994A
-1.2V     -3.383A    -4.084A    -2.934A
-1.16V    -2.841A    -3.655A    -2.294A
-1.12V    -2.299A    -3.226A    -1.656A
-1.04V    -1.218A    -2.369A    -414.2mA
-1V       -684.7mA   -1.941A    -119.2mA
-960mV    -257.2mA   -1.514A    -45.66mA
-920mV    -87.03mA   -1.089A    -28.93mA
-840mV    -19.35mA   -312.8mA   -18.97mA
-800mV    -13.55mA   -132.4mA   -15.49mA
-720mV    -8.042mA   -25.67mA   -9.491mA
1.8V      0A         13.64nA    0A
[POWER_clamp]
|Voltage   I(typ)   I(min)   I(max)
-1.8V     470.8mA    433.7mA    554.6mA
-1.14V    95.25mA    122.7mA    82.82mA
-1.12V    84.97mA    114mA      70.27mA
-1.06V    55.51mA    88.42mA    35.67mA
-1.04V    46.34mA    80.15mA    25.76mA
-1V       29.51mA    64.13mA    10.3mA
-940mV    10.39mA    41.86mA    1.109mA
-900mV    3.624mA    28.77mA    182.8uA
-840mV    490.7uA    13.24mA    11.35uA
-800mV    116.8uA    6.532mA    1.77uA
-740mV    13.2uA     1.724mA    109.3nA
0V        0A         18.75nA    0A
[Ramp]
| variable   typ   min   max
dV/dt_r  0.79770/0.83589n   0.58660/1.80071n   0.97662/0.45060n
dV/dt_f  0.83149/0.68728n   0.56073/1.54104n   1.02769/0.40019n
R_load = 50.000000
[Rising Waveform]
R_fixture= 50.000000
V_fixture= 1.800000
V_fixture_min= 1.600000
V_fixture_max= 2.000000
|time   V(typ)   V(min)   V(max)
0s        414mV      656.9mV    287.3mV
450.5ps   414.3mV    657.1mV    453.4mV
560.6ps   448.9mV    657.1mV    810.4mV
740.7ps   581.5mV    656.1mV    1.74V
900.9ps   891.8mV    654mV      1.958V
1.131ns   1.533V     706.6mV    1.986V
1.401ns   1.756V     893.6mV    1.992V
1.842ns   1.79V      1.371V     1.996V
2.182ns   1.794V     1.544V     1.998V
4.985ns   1.8V       1.6V       1.999V
[Rising Waveform]
R_fixture= 50.000000
V_fixture= 0.0
V_fixture_min= 0.0
V_fixture_max= 0.0
|time   V(typ)   V(min)   V(max)
0s        -42.83uV   -10.24uV   126.9uV
620.6ps   -12.27mV   149.4uV    71.24mV
1.021ns   2.97mV     -9.354mV   892.1mV
1.241ns   121.5mV    -10.71mV   1.343V
1.702ns   586.9mV    -9.153mV   1.56V
2.322ns   1.119V     84.4mV     1.611V
3.063ns   1.274V     364.3mV    1.624V
4.164ns   1.318V     722.8mV    1.627V
5.085ns   1.326V     880.2mV    1.627V
9.97ns    1.33V      980.4mV    1.628V
[Falling Waveform]
R_fixture= 50.000000
V_fixture= 1.800000
V_fixture_min= 1.600000
V_fixture_max= 2.000000
|time   V(typ)   V(min)   V(max)
0s        1.8V       1.6V       1.999V
580.6ps   1.817V     1.6V       1.964V
780.8ps   1.813V     1.601V     1.652V
1.201ns   1.746V     1.613V     593.9mV
1.582ns   1.431V     1.607V     372mV
2.182ns   696.9mV    1.564V     318.6mV
2.843ns   510.7mV    1.371V     300.3mV
3.824ns   448.6mV    946.9mV    291.2mV
4.805ns   428.3mV    783.1mV    288.5mV
9.97ns    414mV      656.9mV    287.3mV
[Falling Waveform]
R_fixture= 50.000000
V_fixture= 0.0
V_fixture_min= 0.0
V_fixture_max= 0.0
|time   V(typ)   V(min)   V(max)
0s        1.33V      980.4mV    1.628V
150.2ps   1.329V     980.4mV    1.622V
290.3ps   1.332V     980.4mV    1.496V
500.5ps   1.269V     980.4mV    1.046V
820.8ps   838.6mV    984.3mV    220.1mV
1.031ns   588.5mV    907.1mV    35.61mV
1.341ns   217.5mV    661.5mV    5.25mV
1.542ns   76.96mV    511.2mV    3.577mV
2.442ns   2.986mV    84.33mV    1.049mV
4.985ns   -42.83uV   -10.24uV   126.9uV
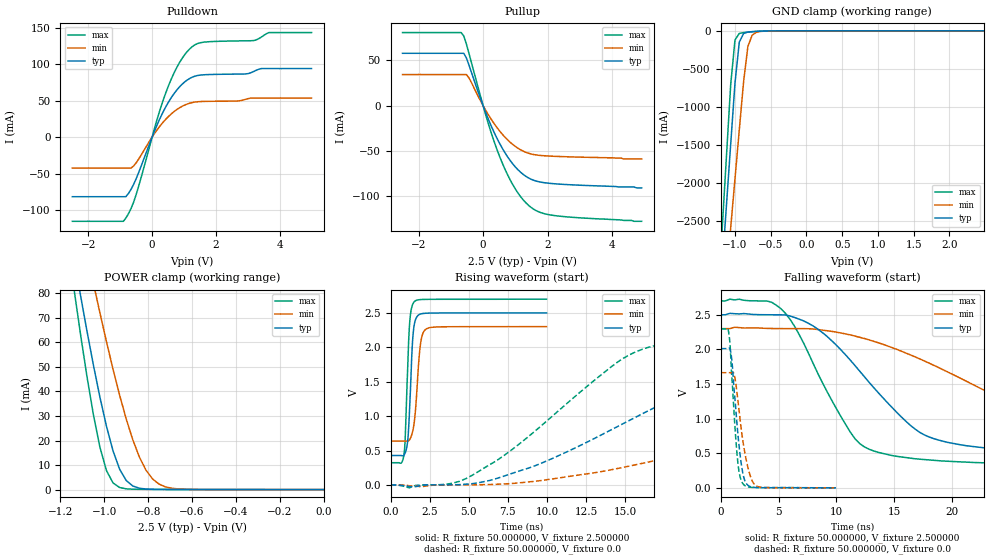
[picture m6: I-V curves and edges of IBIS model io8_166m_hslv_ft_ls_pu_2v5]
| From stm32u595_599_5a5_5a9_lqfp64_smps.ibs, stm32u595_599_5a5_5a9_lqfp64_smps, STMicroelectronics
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|   Model io8_166m_hslv_ft_ls_pu_2v5
[Model]  io8_166m_hslv_ft_ls_pu_2v5
Model_type I/O
Polarity   Non-Inverting
Enable   Active-Low
Vinl =   0.750000V
Vinh =   1.750000V
Vmeas =  1.250000V
Cref =   50.000000pF
Rref =   100.000000M
Vref =   0.0V
C_comp   3.458600pF   3.457900pF   3.495500pF
[Temperature Range]   25.000000   0.140000k   -40.000000
[Pullup Reference]   2.500000V   2.300000V   2.700000V
[Pulldown Reference]   0.0V   0.0V   0.0V
[POWER Clamp Reference]   2.500000V   2.300000V   2.700000V
[GND Clamp Reference]   0.0V   0.0V   0.0V
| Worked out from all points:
|   slope of the pulldown table from 0 to 0.375 V, typ, clamps not added: 10.1 ohm
|   slope of the pullup table from 0 to 0.375 V, typ, clamps not added: 11.7 ohm
|   GND clamp passes 1 mA (typ) near -0.50 V on its own axis
|   POWER clamp passes 1 mA (typ) near -0.85 V on its own axis
|   rising waveform, R_fixture 50.000000, V_fixture 2.500000: 20-80 % time 246ps typ, 327ps min, 230ps max; typ from 0.428 V to 2.5 V
|   rising waveform, R_fixture 50.000000, V_fixture 0.0: 20-80 % time 11.1ns typ, 20ns min, 7.41ns max; typ from 0 V to 2.01 V
|   falling waveform, R_fixture 50.000000, V_fixture 2.500000: 20-80 % time 7.02ns typ, 13.9ns min, 4.49ns max; typ from 2.5 V to 0.428 V
|   falling waveform, R_fixture 50.000000, V_fixture 0.0: 20-80 % time 660ps typ, 863ps min, 544ps max; typ from 2.01 V to 0 V
[Pulldown]
|Voltage   I(typ)   I(min)   I(max)
-2.5V     -81.62mA   -42.31mA   -115.3mA
-900mV    -81.62mA   -42.31mA   -115.3mA
-820mV    -81.43mA   -42.31mA   -110.6mA
-500mV    -56.95mA   -35.08mA   -78.57mA
140mV     15.18mA    9.02mA     22.02mA
460mV     44mA       25.98mA    64.38mA
860mV     68.91mA    40.27mA    102.2mA
1.26V     82.21mA    47.42mA    124mA
1.66V     85.54mA    48.99mA    130.3mA
3.18V     89.84mA    53.62mA    132.3mA
3.66V     93.97mA    53.62mA    143.3mA
5V        93.97mA    53.62mA    143.3mA
[Pullup]
|Voltage   I(typ)   I(min)   I(max)
-2.5V     57.98mA    34.47mA    80.9mA
-680mV    57.98mA    34.47mA    80.9mA
-600mV    57.98mA    34.47mA    77.13mA
-440mV    45.11mA    30.85mA    58.07mA
120mV     -11.17mA   -7.509mA   -14.95mA
520mV     -42.31mA   -28.36mA   -56.92mA
760mV     -56.64mA   -37.85mA   -76.55mA
1V        -67.83mA   -45.13mA   -92.22mA
1.48V     -81.29mA   -53.4mA    -112.4mA
1.8V      -84.73mA   -55.19mA   -118.5mA
2.28V     -86.63mA   -56.16mA   -121.9mA
4.92V     -91mA      -59mA      -128mA
[GND_clamp]
|Voltage   I(typ)   I(min)   I(max)
-2.5V     -9.641A    -9.693A    -9.352A
-1.18V    -3.114A    -3.874A    -2.614A
-1.12V    -2.301A    -3.23A     -1.656A
-1.06V    -1.489A    -2.587A    -706.2mA
-1V       -685.8mA   -1.945A    -119.3mA
-940mV    -149.7mA   -1.304A    -34.73mA
-880mV    -35.54mA   -672.6mA   -23.06mA
-820mV    -16.2mA    -206.4mA   -17.27mA
-760mV    -10.58mA   -57.55mA   -12.41mA
-700mV    -7.152mA   -18.74mA   -8.24mA
-400mV    -103.3uA   -378.6uA   -41.75uA
2.48V     0A         13.22nA    0A
[POWER_clamp]
|Voltage   I(typ)   I(min)   I(max)
-2.49V    881.1mA    773.1mA    1.07A
-1.14V    95.32mA    122.8mA    82.93mA
-1.11V    79.97mA    109.7mA    64.26mA
-1.05V    50.95mA    84.3mA     30.69mA
-1.02V    37.7mA     72.08mA    17.29mA
-990mV    25.79mA    60.29mA    7.738mA
-930mV    8.312mA    38.47mA    853.1uA
-900mV    3.712mA    28.81mA    313.6uA
-840mV    566.2uA    13.29mA    123.7uA
-780mV    119uA      4.365mA    94.04uA
-660mV    38.98uA    251.5uA    57.76uA
0V        0A         18.93nA    0A
[Ramp]
| variable   typ   min   max
dV/dt_r  1.20650/11.06197n   0.99759/19.94487n   1.37763/7.40648n
dV/dt_f  1.24314/7.00178n   0.99710/13.86844n   1.42607/4.47779n
R_load = 50.000000
[Rising Waveform]
R_fixture= 50.000000
V_fixture= 2.500000
V_fixture_min= 2.300000
V_fixture_max= 2.700000
|time   V(typ)   V(min)   V(max)
0s        428.1mV    638.2mV    323.2mV
840.8ps   428.9mV    638.2mV    416.6mV
940.9ps   469.3mV    637.7mV    717.5mV
1.101ns   656.7mV    635.8mV    1.742V
1.201ns   1.033V     653mV      2.293V
1.381ns   1.998V     751.3mV    2.604V
1.522ns   2.336V     923.9mV    2.664V
1.902ns   2.483V     2.027V     2.693V
2.262ns   2.495V     2.263V     2.696V
9.97ns    2.5V       2.3V       2.7V
[Rising Waveform]
R_fixture= 50.000000
V_fixture= 0.0
V_fixture_min= 0.0
V_fixture_max= 0.0
|time   V(typ)   V(min)   V(max)
0s        472uV      557.8uV    453.4uV
3.604ns   1.843mV    1.426mV    11.29mV
5.205ns   18.45mV    2.604mV    138.9mV
9.61ns    313.3mV    64.12mV    855.2mV
15.62ns   978.5mV    291.3mV    1.928V
20.42ns   1.507V     537.9mV    2.16V
24.02ns   1.745V     734.2mV    2.223V
37.64ns   1.96V      1.366V     2.288V
53.25ns   2.002V     1.574V     2.296V
199.4ns   2.011V     1.663V     2.296V
[Falling Waveform]
R_fixture= 50.000000
V_fixture= 2.500000
V_fixture_min= 2.300000
V_fixture_max= 2.700000
|time   V(typ)   V(min)   V(max)
0s        2.5V       2.3V       2.7V
5.205ns   2.499V     2.3V       2.588V
6.406ns   2.46V      2.3V       2.327V
8.408ns   2.291V     2.287V     1.649V
12.01ns   1.687V     2.175V     640.7mV
16.42ns   901.2mV    1.919V     429.3mV
19.22ns   673.9mV    1.707V     388.1mV
29.23ns   502.2mV    983.7mV    339.6mV
44.84ns   446.9mV    745.3mV    326mV
199.4ns   428.1mV    638.2mV    323.2mV
[Falling Waveform]
R_fixture= 50.000000
V_fixture= 0.0
V_fixture_min= 0.0
V_fixture_max= 0.0
|time   V(typ)   V(min)   V(max)
0s        2.011V     1.663V     2.296V
620.6ps   2.011V     1.663V     2.297V
780.8ps   2.014V     1.663V     2.123V
880.9ps   1.946V     1.663V     1.849V
1.181ns   1.374V     1.626V     1.012V
1.461ns   822.1mV    1.297V     401.6mV
1.922ns   205.1mV    673.4mV    60.46mV
2.482ns   24.26mV    214.3mV    11.14mV
3.083ns   5.257mV    28.25mV    5.665mV
9.97ns    472uV      557.8uV    453.4uV
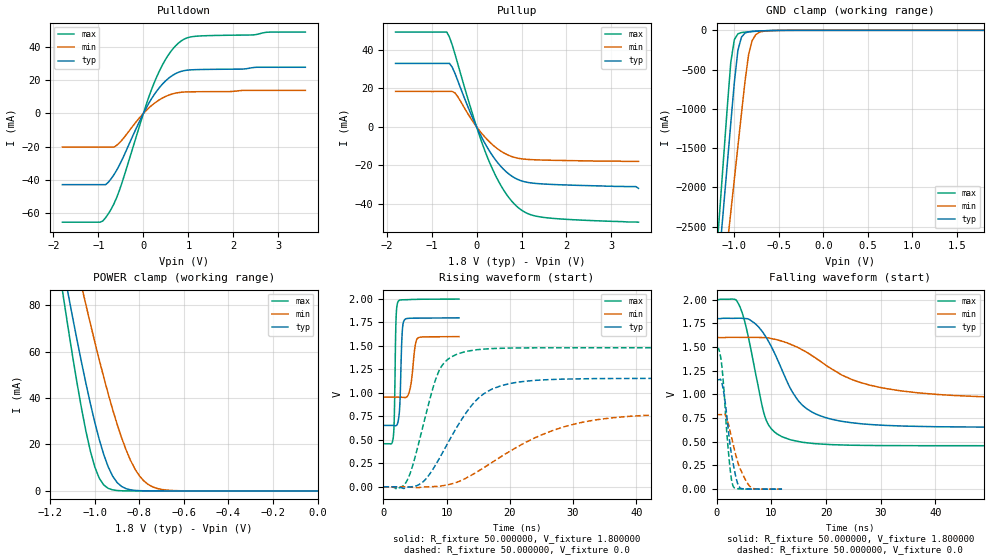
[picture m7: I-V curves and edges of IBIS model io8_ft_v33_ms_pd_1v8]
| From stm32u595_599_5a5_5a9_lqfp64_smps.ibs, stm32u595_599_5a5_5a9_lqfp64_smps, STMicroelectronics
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|   Model io8_ft_v33_ms_pd_1v8
[Model]  io8_ft_v33_ms_pd_1v8
Model_type I/O
Polarity   Non-Inverting
Enable   Active-Low
Vinl =   0.540000V
Vinh =   1.260000V
Vmeas =  0.900000V
Cref =   50.000000pF
Rref =   100.000000M
Vref =   0.0V
C_comp   3.087500pF   3.086600pF   3.135700pF
[Temperature Range]   25.000000   0.140000k   -40.000000
[Pullup Reference]   1.800000V   1.600000V   2.000000V
[Pulldown Reference]   0.0V   0.0V   0.0V
[POWER Clamp Reference]   1.800000V   1.600000V   2.000000V
[GND Clamp Reference]   0.0V   0.0V   0.0V
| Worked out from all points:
|   slope of the pulldown table from 0 to 0.27 V, typ, clamps not added: 21.7 ohm
|   slope of the pullup table from 0 to 0.27 V, typ, clamps not added: 22.6 ohm
|   GND clamp passes 1 mA (typ) near -0.51 V on its own axis
|   POWER clamp passes 1 mA (typ) near -0.86 V on its own axis
|   rising waveform, R_fixture 50.000000, V_fixture 1.800000: 20-80 % time 316ps typ, 627ps min, 226ps max; typ from 0.654 V to 1.8 V
|   rising waveform, R_fixture 50.000000, V_fixture 0.0: 20-80 % time 6.48ns typ, 13.4ns min, 3.57ns max; typ from 0 V to 1.15 V
|   falling waveform, R_fixture 50.000000, V_fixture 1.800000: 20-80 % time 6.36ns typ, 13.4ns min, 3.36ns max; typ from 1.8 V to 0.654 V
|   falling waveform, R_fixture 50.000000, V_fixture 0.0: 20-80 % time 1.6ns typ, 2.38ns min, 1.17ns max; typ from 1.15 V to 0 V
[Pulldown]
|Voltage   I(typ)   I(min)   I(max)
-1.8V     -42.74mA   -20.21mA   -65.25mA
-960mV    -42.74mA   -20.21mA   -65.25mA
-780mV    -41.3mA    -20.21mA   -60.25mA
-660mV    -37mA      -20.2mA    -54.5mA
-540mV    -31.39mA   -17.82mA   -46.65mA
0V        0A         0A         0A
240mV     11.28mA    6.002mA    18.38mA
480mV     19.17mA    10.02mA    31.83mA
780mV     24.67mA    12.5mA     42.21mA
960mV     25.9mA     12.9mA     45.21mA
1.14V     26.24mA    12.99mA    46.23mA
3.6V      27.69mA    13.82mA    48.79mA
[Pullup]
|Voltage   I(typ)   I(min)   I(max)
-1.8V     32.87mA    18.3mA     49.14mA
-660mV    32.87mA    18.3mA     49.14mA
-600mV    32.87mA    18.3mA     46.41mA
-480mV    27.73mA    17.56mA    37.8mA
-60mV     3.108mA    1.975mA    4.436mA
240mV     -10.82mA   -6.752mA   -15.73mA
420mV     -17.18mA   -10.64mA   -25.23mA
600mV     -22.1mA    -13.54mA   -32.82mA
960mV     -27.82mA   -16.55mA   -42.66mA
1.2V      -29.16mA   -17.09mA   -45.68mA
1.56V     -29.85mA   -17.37mA   -47.3mA
3.6V      -32mA      -18mA      -49.6mA
[GND_clamp]
|Voltage   I(typ)   I(min)   I(max)
-1.8V     -9.707A    -9.942A    -9.774A
-1.2V     -3.309A    -4.006A    -2.865A
-1.16V    -2.777A    -3.584A    -2.239A
-1.12V    -2.246A    -3.162A    -1.614A
-1.04V    -1.186A    -2.319A    -408.7mA
-1V       -663.9mA   -1.898A    -117.8mA
-960mV    -254mA     -1.478A    -45.15mA
-920mV    -86.04mA   -1.06A     -28.6mA
-840mV    -19.13mA   -308.9mA   -18.75mA
-800mV    -13.4mA    -130.8mA   -15.33mA
-720mV    -7.959mA   -25.38mA   -9.395mA
1.8V      45.71uA    33.33uA    56.11uA
[POWER_clamp]
|Voltage   I(typ)   I(min)   I(max)
-1.8V     470.8mA    433.7mA    554.6mA
-1.14V    95.25mA    122.7mA    82.82mA
-1.12V    84.97mA    114mA      70.27mA
-1.06V    55.51mA    88.42mA    35.67mA
-1.04V    46.34mA    80.15mA    25.76mA
-1V       29.51mA    64.13mA    10.3mA
-940mV    10.39mA    41.86mA    1.109mA
-900mV    3.624mA    28.77mA    182.8uA
-840mV    490.7uA    13.24mA    11.35uA
-800mV    116.8uA    6.532mA    1.77uA
-740mV    13.2uA     1.723mA    109.3nA
0V        0A         18.72nA    0A
[Ramp]
| variable   typ   min   max
dV/dt_r  0.69258/6.47390n   0.47160/13.35196n   0.88830/3.56483n
dV/dt_f  0.68756/6.35251n   0.38612/13.40870n   0.92452/3.35331n
R_load = 50.000000
[Rising Waveform]
R_fixture= 50.000000
V_fixture= 1.800000
V_fixture_min= 1.600000
V_fixture_max= 2.000000
|time   V(typ)   V(min)   V(max)
0s        653.5mV    954.4mV    458.5mV
1.586ns   652.9mV    954.4mV    541.5mV
1.73ns    651.8mV    954.5mV    759.2mV
1.994ns   650.5mV    954.5mV    1.775V
2.33ns    697.7mV    954.4mV    1.973V
2.619ns   900.4mV    954.2mV    1.988V
2.979ns   1.646V     953.1mV    1.991V
3.315ns   1.776V     950.7mV    1.992V
5.405ns   1.796V     1.582V     1.996V
11.96ns   1.799V     1.599V     1.999V
[Rising Waveform]
R_fixture= 50.000000
V_fixture= 0.0
V_fixture_min= 0.0
V_fixture_max= 0.0
|time   V(typ)   V(min)   V(max)
0s        4.579uV    -1.111uV   13.17uV
3.524ns   -10.55mV   -392uV     40.55mV
4.645ns   1.297mV    -5.615mV   228.6mV
6.246ns   51.54mV    -2.599mV   641.6mV
8.809ns   296.8mV    6.052mV    1.237V
13.13ns   792.3mV    94.58mV    1.443V
18.74ns   1.079V     325.9mV    1.475V
25.47ns   1.139V     564.8mV    1.48V
33.47ns   1.152V     710.8mV    1.48V
79.76ns   1.154V     786.2mV    1.48V
[Falling Waveform]
R_fixture= 50.000000
V_fixture= 1.800000
V_fixture_min= 1.600000
V_fixture_max= 2.000000
|time   V(typ)   V(min)   V(max)
0s        1.799V     1.599V     1.999V
4.004ns   1.803V     1.602V     1.956V
5.445ns   1.799V     1.601V     1.7V
8.969ns   1.61V      1.598V     744.2mV
13.45ns   1.067V     1.53V      521.8mV
15.7ns    885.3mV    1.469V     494.7mV
19.06ns   771.5mV    1.345V     476.2mV
24.66ns   701mV      1.158V     463.5mV
33.63ns   666.7mV    1.037V     459.3mV
79.76ns   653.5mV    954.4mV    458.5mV
[Falling Waveform]
R_fixture= 50.000000
V_fixture= 0.0
V_fixture_min= 0.0
V_fixture_max= 0.0
|time   V(typ)   V(min)   V(max)
0s        1.154V     786.2mV    1.48V
432.4ps   1.154V     786.2mV    1.474V
961ps     1.123V     786mV      1.305V
1.586ns   916.2mV    786.2mV    843.3mV
2.282ns   557.1mV    660.3mV    327mV
2.715ns   370.7mV    554.6mV    108mV
3.051ns   265.6mV    471mV      29.01mV
4.06ns    31.37mV    253.7mV    3.752mV
6.318ns   1.411mV    17.5mV     664.1uV
11.96ns   4.579uV    -1.111uV   13.17uV
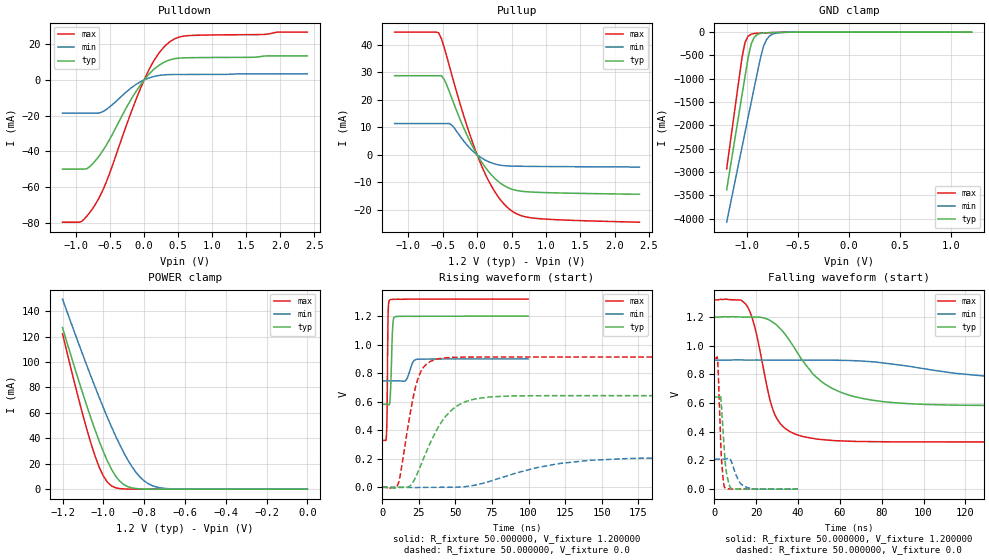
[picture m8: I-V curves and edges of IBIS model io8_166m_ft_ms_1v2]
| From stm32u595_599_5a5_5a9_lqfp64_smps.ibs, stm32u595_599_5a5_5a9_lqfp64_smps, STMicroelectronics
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|   Model io8_166m_ft_ms_1v2
[Model]  io8_166m_ft_ms_1v2
Model_type I/O
Polarity   Non-Inverting
Enable   Active-Low
Vinl =   0.360000V
Vinh =   0.840000V
Vmeas =  0.600000V
Cref =   50.000000pF
Rref =   100.000000M
Vref =   0.0V
C_comp   3.151500pF   3.086800pF   3.197700pF
[Temperature Range]   25.000000   0.140000k   -40.000000
[Pullup Reference]   1.200000V   0.900000V   1.320000V
[Pulldown Reference]   0.0V   0.0V   0.0V
[POWER Clamp Reference]   1.200000V   0.900000V   1.320000V
[GND Clamp Reference]   0.0V   0.0V   0.0V
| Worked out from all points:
|   slope of the pulldown table from 0 to 0.18 V, typ, clamps not added: 25.4 ohm
|   slope of the pullup table from 0 to 0.18 V, typ, clamps not added: 27.8 ohm
|   GND clamp passes 1 mA (typ) near -0.51 V on its own axis
|   POWER clamp passes 1 mA (typ) near -0.86 V on its own axis
|   rising waveform, R_fixture 50.000000, V_fixture 1.200000: 20-80 % time 1.13ns typ, 3.03ns min, 564ps max; typ from 0.582 V to 1.2 V
|   rising waveform, R_fixture 50.000000, V_fixture 0.0: 20-80 % time 19.5ns typ, 48.3ns min, 9.6ns max; typ from 0 V to 0.643 V
|   falling waveform, R_fixture 50.000000, V_fixture 1.200000: 20-80 % time 22.1ns typ, 55.1ns min, 9.25ns max; typ from 1.2 V to 0.582 V
|   falling waveform, R_fixture 50.000000, V_fixture 0.0: 20-80 % time 1.97ns typ, 3.67ns min, 1.48ns max; typ from 0.643 V to 0 V
[Pulldown]
|Voltage   I(typ)   I(min)   I(max)
-1.2V     -49.86mA   -18.57mA   -79.57mA
-920mV    -49.86mA   -18.57mA   -79.2mA
-840mV    -49.6mA    -18.57mA   -76.08mA
-720mV    -45.32mA   -18.57mA   -69.74mA
-560mV    -36.71mA   -16.58mA   -57.44mA
-200mV    -11.43mA   -4.74mA    -19.03mA
0V        0A         -500fA     0A
160mV     6.477mA    2.075mA    11.78mA
360mV     10.99mA    2.99mA     20.81mA
480mV     12.07mA    3.054mA    23.53mA
640mV     12.43mA    3.075mA    24.76mA
2.4V      13.46mA    3.369mA    26.78mA
[Pullup]
|Voltage   I(typ)   I(min)   I(max)
-1.2V     28.72mA    11.35mA    44.55mA
-560mV    28.72mA    11.35mA    44.33mA
-480mV    27.44mA    11.35mA    39.12mA
-360mV    20.01mA    10.56mA    28.26mA
-160mV    7.809mA    3.931mA    11.44mA
40mV      -1.649mA   -721.3uA   -2.521mA
240mV     -8.14mA    -3.2mA     -12.72mA
360mV     -10.68mA   -3.85mA    -16.99mA
480mV     -12.27mA   -4.078mA   -19.94mA
640mV     -13.22mA   -4.169mA   -22.09mA
880mV     -13.63mA   -4.231mA   -23.14mA
2.36V     -14.3mA    -4.5mA     -24.47mA
[GND_clamp]
|Voltage   I(typ)   I(min)   I(max)
-1.2V     -3.379A    -4.076A    -2.932A
-1.05V    -1.35A     -2.47A     -550.7mA
-1.02V    -947.8mA   -2.149A    -221.5mA
-990mV    -552.4mA   -1.829A    -88.44mA
-960mV    -255.3mA   -1.51A     -44.87mA
-930mV    -111.8mA   -1.191A    -30.68mA
-870mV    -28.36mA   -564.6mA   -21.34mA
-840mV    -18.65mA   -309.5mA   -18.49mA
-810mV    -14.07mA   -161.6mA   -15.92mA
-780mV    -11.37mA   -83.33mA   -13.53mA
-600mV    -3.009mA   -4.322mA   -3.091mA
1.2V      0A         13.65nA    0A
[POWER_clamp]
|Voltage   I(typ)   I(min)   I(max)
-1.2V     127mA      149.4mA    122.2mA
-1.12V    84.97mA    114mA      70.27mA
-1.06V    55.51mA    88.42mA    35.67mA
-1.02V    37.63mA    72.04mA    17.17mA
-1V       29.51mA    64.13mA    10.3mA
-960mV    15.69mA    48.99mA    2.571mA
-900mV    3.624mA    28.77mA    182.8uA
-840mV    490.7uA    13.24mA    11.35uA
-800mV    116.8uA    6.532mA    1.77uA
-740mV    13.2uA     1.724mA    109.1nA
-620mV    167.4nA    79.36uA    0A
0V        0A         17.87nA    0A
[Ramp]
| variable   typ   min   max
dV/dt_r  0.38561/19.47629n   0.12547/48.28870n   0.54824/9.58896n
dV/dt_f  0.37086/22.03199n   92.21400m/55.10748n 0.59438/9.21659n
R_load = 50.000000
[Rising Waveform]
R_fixture= 50.000000
V_fixture= 1.200000
V_fixture_min= 0.900000
V_fixture_max= 1.320000
|time   V(typ)   V(min)   V(max)
0s        581.9mV    745.9mV    329.4mV
2.803ns   582mV      745.9mV    367.5mV
3.203ns   582mV      745.9mV    512.8mV
3.604ns   581.5mV    745.9mV    959.8mV
4.004ns   580.1mV    745.9mV    1.243V
5.005ns   589.2mV    745.9mV    1.313V
7.007ns   1.115V     745.9mV    1.318V
8.408ns   1.194V     745.9mV    1.318V
23.22ns   1.199V     897mV      1.32V
99.7ns    1.2V       900mV      1.32V
[Rising Waveform]
R_fixture= 50.000000
V_fixture= 0.0
V_fixture_min= 0.0
V_fixture_max= 0.0
|time   V(typ)   V(min)   V(max)
0s        1.93uV     1.554uV    1.951uV
10.21ns   -994uV     -492.1nV   9.235mV
18.02ns   4.427mV    -1.107mV   455.7mV
23.42ns   85.94mV    -1.798mV   731.7mV
28.23ns   203.7mV    -311.5uV   842.7mV
36.04ns   380.3mV    -48.46uV   895.2mV
50.45ns   566mV      1.031mV    911.5mV
73.87ns   634mV      43.58mV    913.7mV
141.7ns   642.6mV    189.2mV    913.7mV
299.1ns   642.7mV    209.3mV    913.8mV
[Falling Waveform]
R_fixture= 50.000000
V_fixture= 1.200000
V_fixture_min= 0.900000
V_fixture_max= 1.320000
|time   V(typ)   V(min)   V(max)
0s        1.2V       900mV      1.32V
15.62ns   1.2V       900.6mV    1.278V
19.22ns   1.2V       900.8mV    1.134V
25.83ns   1.182V     900.5mV    667.7mV
28.83ns   1.155V     900.3mV    522.1mV
42.64ns   886.4mV    900mV      365.7mV
58.26ns   689.3mV    899mV      337.9mV
84.68ns   604.6mV    872.8mV    330mV
153.2ns   582.2mV    767.8mV    329.4mV
299.1ns   581.9mV    745.9mV    329.4mV
[Falling Waveform]
R_fixture= 50.000000
V_fixture= 0.0
V_fixture_min= 0.0
V_fixture_max= 0.0
|time   V(typ)   V(min)   V(max)
0s        642.7mV    209.3mV    913.8mV
1.522ns   642.7mV    209.3mV    895.7mV
2.803ns   655.6mV    209.3mV    407.4mV
3.283ns   590.8mV    209.3mV    231.4mV
4.885ns   237.1mV    208.9mV    11.45mV
5.926ns   100.7mV    211.4mV    3.714mV
8.168ns   4.329mV    189.3mV    1.207mV
11.85ns   708.3uV    51.63mV    845.8uV
15.22ns   289.1uV    14.74mV    762.5uV
39.88ns   1.93uV     1.554uV    1.951uV
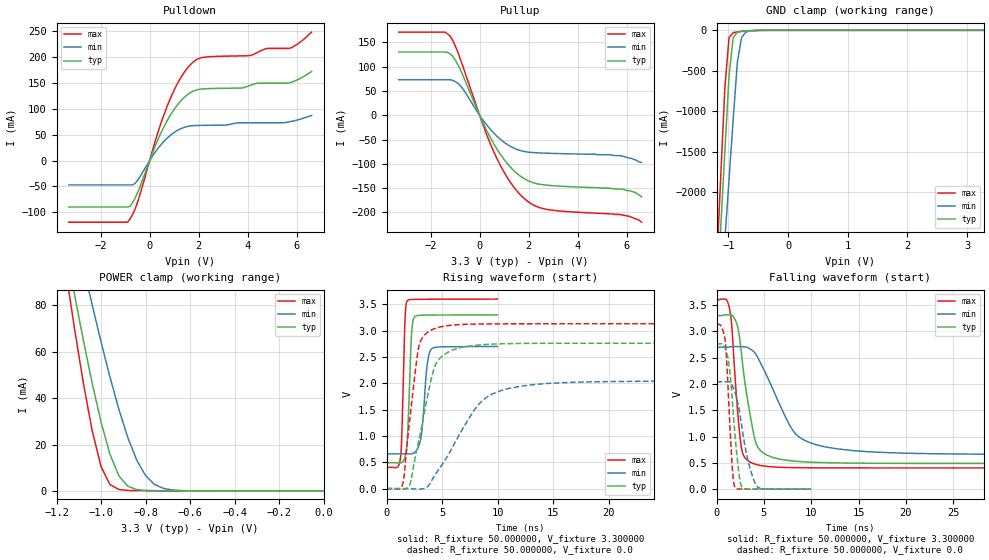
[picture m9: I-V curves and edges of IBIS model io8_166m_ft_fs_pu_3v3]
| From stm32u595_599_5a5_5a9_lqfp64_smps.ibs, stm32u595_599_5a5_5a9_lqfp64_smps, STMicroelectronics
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|   Model io8_166m_ft_fs_pu_3v3
[Model]  io8_166m_ft_fs_pu_3v3
Model_type I/O
Polarity   Non-Inverting
Enable   Active-Low
Vinl =   0.990000V
Vinh =   2.310000V
Vmeas =  1.650000V
Cref =   50.000000pF
Rref =   100.000000M
Vref =   0.0V
C_comp   3.517200pF   3.489400pF   3.557800pF
[Temperature Range]   25.000000   0.140000k   -40.000000
[Pullup Reference]   3.300000V   2.700000V   3.600000V
[Pulldown Reference]   0.0V   0.0V   0.0V
[POWER Clamp Reference]   3.300000V   2.700000V   3.600000V
[GND Clamp Reference]   0.0V   0.0V   0.0V
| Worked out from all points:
|   slope of the pulldown table from 0 to 0.495 V, typ, clamps not added: 8.73 ohm
|   slope of the pullup table from 0 to 0.495 V, typ, clamps not added: 9.64 ohm
|   GND clamp passes 1 mA (typ) near -0.50 V on its own axis
|   POWER clamp passes 1 mA (typ) near -0.85 V on its own axis
|   rising waveform, R_fixture 50.000000, V_fixture 3.300000: 20-80 % time 302ps typ, 460ps min, 243ps max; typ from 0.49 V to 3.3 V
|   rising waveform, R_fixture 50.000000, V_fixture 0.0: 20-80 % time 1.63ns typ, 3.59ns min, 1.01ns max; typ from 0.001 V to 2.76 V
|   falling waveform, R_fixture 50.000000, V_fixture 3.300000: 20-80 % time 1.39ns typ, 3.34ns min, 786ps max; typ from 3.3 V to 0.49 V
|   falling waveform, R_fixture 50.000000, V_fixture 0.0: 20-80 % time 788ps typ, 1.27ns min, 541ps max; typ from 2.76 V to 0.001 V
[Pulldown]
|Voltage   I(typ)   I(min)   I(max)
-3.3V     -89.71mA   -47.06mA   -119mA
-900mV    -89.71mA   -47.06mA   -119mA
-500mV    -62.92mA   -38.72mA   -81.44mA
300mV     36.2mA     21.01mA    48.7mA
800mV     84.07mA    46.96mA    114.8mA
1.3V      116.7mA    62.09mA    162.4mA
1.8V      134.4mA    67.39mA    191.2mA
2.3V      138.6mA    67.98mA    199.8mA
4.1V      145.2mA    72.76mA    202.7mA
4.8V      149.3mA    72.76mA    216.4mA
5.7V      149.8mA    74.9mA     216.4mA
6.6V      172mA      87.1mA     247.9mA
[Pullup]
|Voltage   I(typ)   I(min)   I(max)
-3.3V     130.3mA    73.26mA    171.3mA
-1.4V     130.3mA    73.26mA    170.9mA
-1.2V     126mA      73.26mA    163.1mA
-800mV    95.36mA    61.61mA    117.5mA
100mV     -11.39mA   -7.258mA   -14.51mA
600mV     -60.65mA   -37.83mA   -77.68mA
1.2V      -103.6mA   -62.35mA   -134mA
1.9V      -132.8mA   -75.24mA   -174.9mA
2.7V      -143.6mA   -78mA      -193.2mA
5.8V      -152mA     -84mA      -205mA
6.3V      -158mA     -91mA      -212mA
6.6V      -168mA     -97mA      -220mA
[GND_clamp]
|Voltage   I(typ)   I(min)   I(max)
-3.3V     -9.098A    -9.372A    -9.671A
-1.2V     -3.386A    -4.091A    -2.933A
-1.13V    -2.437A    -3.34A     -1.815A
-1.06V    -1.49A     -2.588A    -705.6mA
-990mV    -555.7mA   -1.839A    -89.03mA
-920mV    -88.12mA   -1.093A    -28.78mA
-850mV    -22.35mA   -387.4mA   -19.84mA
-780mV    -12.12mA   -88.01mA   -13.88mA
-710mV    -7.71mA    -22.52mA   -8.846mA
-640mV    -4.545mA   -7.864mA   -4.87mA
-360mV    -31.12uA   -173.5uA   -8.497uA
3.28V     0A         14.15nA    -7.901nA
[POWER_clamp]
|Voltage   I(typ)   I(min)   I(max)
-3.28V    1.355A     1.167A     1.665A
-1.16V    105.8mA    131.6mA    95.87mA
-1.12V    85.08mA    114mA      70.45mA
-1.08V    65.17mA    96.88mA    46.74mA
-1.04V    46.48mA    80.2mA     25.96mA
-1V       29.63mA    64.18mA    10.49mA
-960mV    15.81mA    49.06mA    2.743mA
-920mV    6.481mA    35.16mA    612.1uA
-840mV    577.5uA    13.29mA    137.6uA
-760mV    93.73uA    2.807mA    97.77uA
-640mV    40.05uA    158.9uA    59.33uA
0V        0A         19.33nA    0A
[Ramp]
| variable   typ   min   max
dV/dt_r  1.65687/1.63166n   1.22436/3.58362n   1.87825/1.00502n
dV/dt_f  1.68571/1.38731n   1.22372/3.33115n   1.91753/0.78152n
R_load = 50.000000
[Rising Waveform]
R_fixture= 50.000000
V_fixture= 3.300000
V_fixture_min= 2.700000
V_fixture_max= 3.600000
|time   V(typ)   V(min)   V(max)
0s        490.5mV    660.4mV    404.1mV
1.261ns   489.2mV    660.4mV    597mV
1.662ns   602.1mV    660.2mV    3.207V
1.862ns   912.5mV    659.7mV    3.566V
2.222ns   2.835V     660.5mV    3.592V
2.503ns   3.257V     684.4mV    3.593V
3.123ns   3.293V     1.007V     3.596V
3.624ns   3.295V     2.297V     3.597V
3.984ns   3.296V     2.637V     3.597V
9.97ns    3.3V       2.7V       3.6V
[Rising Waveform]
R_fixture= 50.000000
V_fixture= 0.0
V_fixture_min= 0.0
V_fixture_max= 0.0
|time   V(typ)   V(min)   V(max)
0s        563uV      600.6uV    581.8uV
1.401ns   -8.59mV    635.8uV    54.2mV
1.602ns   -10.07mV   675.2uV    267.5mV
2.102ns   78.25mV    -394.9uV   1.336V
2.903ns   916.5mV    -8.62mV    2.702V
4.004ns   2.066V     130.2mV    3.009V
4.505ns   2.393V     306.4mV    3.052V
8.408ns   2.73V      1.628V     3.126V
12.01ns   2.757V     1.943V     3.131V
49.85ns   2.762V     2.041V     3.131V
[Falling Waveform]
R_fixture= 50.000000
V_fixture= 3.300000
V_fixture_min= 2.700000
V_fixture_max= 3.600000
|time   V(typ)   V(min)   V(max)
0s        3.3V       2.7V       3.6V
1.401ns   3.312V     2.704V     3.411V
1.602ns   3.31V      2.708V     3.131V
2.202ns   3.107V     2.71V      1.535V
2.703ns   2.464V     2.708V     719.5mV
3.904ns   1.066V     2.618V     485.9mV
4.905ns   694.1mV    2.303V     443.2mV
8.108ns   535.9mV    1.105V     410.2mV
11.11ns   505.9mV    819.6mV    405.6mV
49.85ns   490.5mV    660.4mV    404.1mV
[Falling Waveform]
R_fixture= 50.000000
V_fixture= 0.0
V_fixture_min= 0.0
V_fixture_max= 0.0
|time   V(typ)   V(min)   V(max)
0s        2.762V     2.041V     3.131V
520.5ps   2.766V     2.041V     3.085V
920.9ps   2.673V     2.041V     2.81V
1.301ns   2.389V     2.044V     1.612V
1.682ns   1.656V     1.961V     366.6mV
1.962ns   1.008V     1.837V     32.82mV
2.623ns   61.15mV    1.246V     3.19mV
3.343ns   4.104mV    535mV      2.019mV
4.284ns   2.144mV    53.85mV    1.495mV
9.97ns    563uV      600.6uV    581.8uV
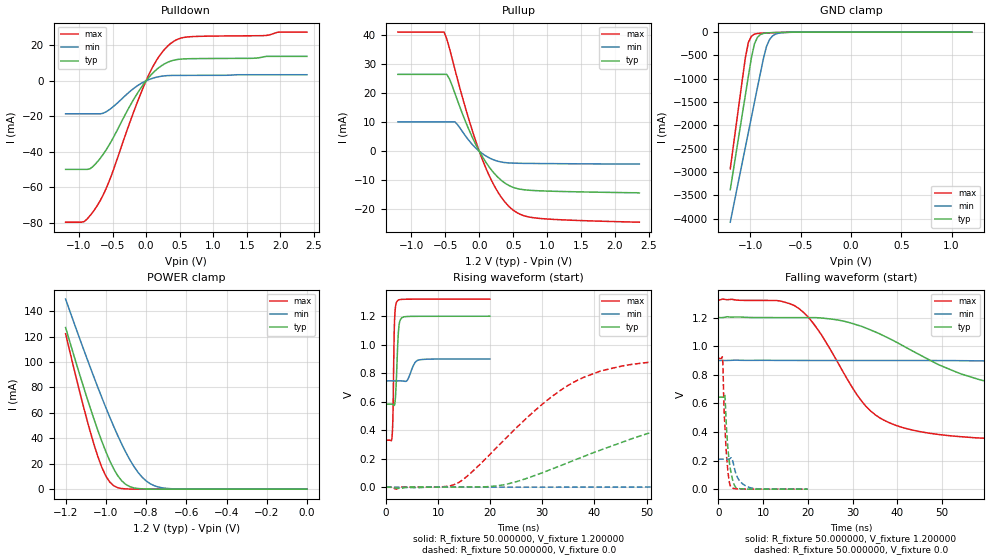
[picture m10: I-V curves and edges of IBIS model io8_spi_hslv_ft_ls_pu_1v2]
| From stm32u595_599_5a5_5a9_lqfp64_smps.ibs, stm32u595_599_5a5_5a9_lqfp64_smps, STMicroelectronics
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|   Model io8_spi_hslv_ft_ls_pu_1v2
[Model]  io8_spi_hslv_ft_ls_pu_1v2
Model_type I/O
Polarity   Non-Inverting
Enable   Active-Low
Vinl =   0.360000V
Vinh =   0.840000V
Vmeas =  0.600000V
Cref =   50.000000pF
Rref =   100.000000M
Vref =   0.0V
C_comp   3.133100pF   3.070300pF   3.178200pF
[Temperature Range]   25.000000   0.140000k   -40.000000
[Pullup Reference]   1.200000V   0.900000V   1.320000V
[Pulldown Reference]   0.0V   0.0V   0.0V
[POWER Clamp Reference]   1.200000V   0.900000V   1.320000V
[GND Clamp Reference]   0.0V   0.0V   0.0V
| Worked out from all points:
|   slope of the pulldown table from 0 to 0.18 V, typ, clamps not added: 25.4 ohm
|   slope of the pullup table from 0 to 0.18 V, typ, clamps not added: 27.8 ohm
|   GND clamp passes 1 mA (typ) near -0.51 V on its own axis
|   POWER clamp passes 1 mA (typ) near -0.86 V on its own axis
|   rising waveform, R_fixture 50.000000, V_fixture 1.200000: 20-80 % time 432ps typ, 1.04ns min, 256ps max; typ from 0.583 V to 1.2 V
|   rising waveform, R_fixture 50.000000, V_fixture 0.0: 20-80 % time 33.7ns typ, 83.1ns min, 17.1ns max; typ from 0 V to 0.643 V
|   falling waveform, R_fixture 50.000000, V_fixture 1.200000: 20-80 % time 30.3ns typ, 71.2ns min, 12.7ns max; typ from 1.2 V to 0.583 V
|   falling waveform, R_fixture 50.000000, V_fixture 0.0: 20-80 % time 1.06ns typ, 1.81ns min, 836ps max; typ from 0.643 V to 0 V
[Pulldown]
|Voltage   I(typ)   I(min)   I(max)
-1.2V     -49.85mA   -18.56mA   -79.56mA
-920mV    -49.85mA   -18.56mA   -79.19mA
-840mV    -49.59mA   -18.56mA   -76.08mA
-720mV    -45.32mA   -18.56mA   -69.73mA
-560mV    -36.71mA   -16.58mA   -57.44mA
-200mV    -11.43mA   -4.738mA   -19.03mA
0V        0A         0A         0A
160mV     6.476mA    2.074mA    11.78mA
360mV     10.99mA    2.987mA    20.81mA
480mV     12.07mA    3.051mA    23.52mA
640mV     12.42mA    3.072mA    24.76mA
2.4V      13.77mA    3.421mA    27.42mA
[Pullup]
|Voltage   I(typ)   I(min)   I(max)
-1.2V     26.52mA    10.15mA    41.1mA
-520mV    26.52mA    10.15mA    41.1mA
-480mV    26.52mA    10.15mA    38.78mA
-440mV    24.95mA    10.15mA    35.49mA
-360mV    19.99mA    10.15mA    28.26mA
-160mV    7.809mA    3.929mA    11.44mA
40mV      -1.649mA   -721.1uA   -2.521mA
240mV     -8.14mA    -3.199mA   -12.72mA
480mV     -12.27mA   -4.076mA   -19.94mA
640mV     -13.22mA   -4.167mA   -22.09mA
880mV     -13.63mA   -4.229mA   -23.13mA
2.36V     -14.4mA    -4.4mA     -24.46mA
[GND_clamp]
|Voltage   I(typ)   I(min)   I(max)
-1.2V     -3.379A    -4.076A    -2.932A
-1.05V    -1.35A     -2.47A     -550.7mA
-1.02V    -947.8mA   -2.149A    -221.5mA
-990mV    -552.4mA   -1.829A    -88.44mA
-960mV    -255.3mA   -1.51A     -44.87mA
-930mV    -111.8mA   -1.191A    -30.68mA
-870mV    -28.35mA   -564.6mA   -21.34mA
-840mV    -18.65mA   -309.5mA   -18.49mA
-810mV    -14.07mA   -161.6mA   -15.92mA
-780mV    -11.37mA   -83.33mA   -13.53mA
-600mV    -3.009mA   -4.321mA   -3.091mA
1.2V      0A         13.65nA    0A
[POWER_clamp]
|Voltage   I(typ)   I(min)   I(max)
-1.2V     127mA      149.4mA    122.2mA
-1.12V    84.98mA    114mA      70.29mA
-1.06V    55.52mA    88.42mA    35.69mA
-1.02V    37.64mA    72.04mA    17.19mA
-1V       29.52mA    64.13mA    10.33mA
-960mV    15.7mA     48.99mA    2.596mA
-900mV    3.636mA    28.77mA    207.8uA
-840mV    502.9uA    13.24mA    43.46uA
-800mV    129uA      6.535mA    43.46uA
-740mV    26.25uA    1.726mA    43.46uA
-620mV    25.09uA    82.33uA    35.76uA
0V        0A         17.36nA    0A
[Ramp]
| variable   typ   min   max
dV/dt_r  0.38570/33.62520n   0.12552/83.02938n   0.54819/17.05907n
dV/dt_f  0.37036/30.29154n   92.32200m/71.12926n 0.59402/12.62730n
R_load = 50.000000
[Rising Waveform]
R_fixture= 50.000000
V_fixture= 1.200000
V_fixture_min= 0.900000
V_fixture_max= 1.320000
|time   V(typ)   V(min)   V(max)
0s        582.7mV    746.2mV    330mV
1.201ns   582.7mV    746.2mV    359.7mV
1.361ns   580.6mV    746.2mV    509.6mV
1.562ns   574.5mV    746.2mV    1.013V
1.682ns   579.9mV    746.2mV    1.184V
2.162ns   897mV      746.2mV    1.305V
2.523ns   1.135V     746.3mV    1.315V
3.243ns   1.193V     745.3mV    1.318V
6.366ns   1.199V     893.5mV    1.32V
19.94ns   1.2V       900mV      1.32V
[Rising Waveform]
R_fixture= 50.000000
V_fixture= 0.0
V_fixture_min= 0.0
V_fixture_max= 0.0
|time   V(typ)   V(min)   V(max)
0s        434.2uV    496uV      378.8uV
13.01ns   1.301mV    820.8uV    17.08mV
23.02ns   19.78mV    855.7uV    344.2mV
36.04ns   188.2mV    1.066mV    737.3mV
45.05ns   312.3mV    1.279mV    848.5mV
57.06ns   447.6mV    3.451mV    894.2mV
84.08ns   595.1mV    34.03mV    912.3mV
127.1ns   639.1mV    112.8mV    914mV
244.2ns   643.2mV    201.5mV    914mV
498.5ns   643.3mV    209.9mV    914mV
[Falling Waveform]
R_fixture= 50.000000
V_fixture= 1.200000
V_fixture_min= 0.900000
V_fixture_max= 1.320000
|time   V(typ)   V(min)   V(max)
0s        1.2V       900mV      1.32V
17.02ns   1.2V       900.2mV    1.284V
22.02ns   1.199V     900mV      1.126V
31.03ns   1.148V     900mV      657.5mV
35.04ns   1.1V       900mV      520.9mV
43.04ns   971.9mV    900mV      415.9mV
57.06ns   778.3mV    897.9mV    360.2mV
81.08ns   650.7mV    875.3mV    336.2mV
124.1ns   594.6mV    802.3mV    330.3mV
498.5ns   582.7mV    746.2mV    330mV
[Falling Waveform]
R_fixture= 50.000000
V_fixture= 0.0
V_fixture_min= 0.0
V_fixture_max= 0.0
|time   V(typ)   V(min)   V(max)
0s        643.3mV    209.9mV    914mV
961ps     643.4mV    209.9mV    919.8mV
1.321ns   653.7mV    210mV      550.1mV
1.481ns   654.3mV    210mV      452.6mV
1.762ns   484.8mV    210mV      284.6mV
2.242ns   260.9mV    209.7mV    105.4mV
2.803ns   125.5mV    218mV      18.33mV
3.924ns   12.73mV    111.5mV    3.22mV
6.727ns   831.3uV    15.06mV    1.219mV
19.94ns   434.2uV    496uV      378.8uV
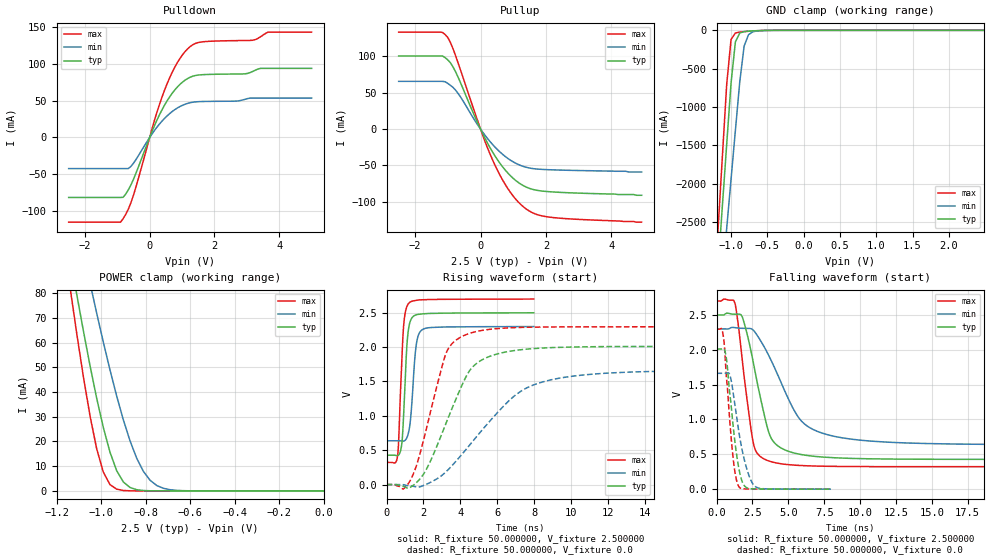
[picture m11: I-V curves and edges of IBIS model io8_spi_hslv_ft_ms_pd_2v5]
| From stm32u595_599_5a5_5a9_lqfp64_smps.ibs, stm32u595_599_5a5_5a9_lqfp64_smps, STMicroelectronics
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|   Model io8_spi_hslv_ft_ms_pd_2v5
[Model]  io8_spi_hslv_ft_ms_pd_2v5
Model_type I/O
Polarity   Non-Inverting
Enable   Active-Low
Vinl =   0.750000V
Vinh =   1.750000V
Vmeas =  1.250000V
Cref =   50.000000pF
Rref =   100.000000M
Vref =   0.0V
C_comp   3.438200pF   3.436700pF   3.473300pF
[Temperature Range]   25.000000   0.140000k   -40.000000
[Pullup Reference]   2.500000V   2.300000V   2.700000V
[Pulldown Reference]   0.0V   0.0V   0.0V
[POWER Clamp Reference]   2.500000V   2.300000V   2.700000V
[GND Clamp Reference]   0.0V   0.0V   0.0V
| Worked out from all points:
|   slope of the pulldown table from 0 to 0.375 V, typ, clamps not added: 10.1 ohm
|   slope of the pullup table from 0 to 0.375 V, typ, clamps not added: 11.7 ohm
|   GND clamp passes 1 mA (typ) near -0.50 V on its own axis
|   POWER clamp passes 1 mA (typ) near -0.86 V on its own axis
|   rising waveform, R_fixture 50.000000, V_fixture 2.500000: 20-80 % time 226ps typ, 273ps min, 223ps max; typ from 0.427 V to 2.5 V
|   rising waveform, R_fixture 50.000000, V_fixture 0.0: 20-80 % time 1.91ns typ, 3.39ns min, 1.31ns max; typ from 0 V to 2.01 V
|   falling waveform, R_fixture 50.000000, V_fixture 2.500000: 20-80 % time 1.31ns typ, 2.44ns min, 855ps max; typ from 2.5 V to 0.427 V
|   falling waveform, R_fixture 50.000000, V_fixture 0.0: 20-80 % time 652ps typ, 856ps min, 532ps max; typ from 2.01 V to 0 V
[Pulldown]
|Voltage   I(typ)   I(min)   I(max)
-2.5V     -81.62mA   -42.31mA   -115.3mA
-900mV    -81.62mA   -42.31mA   -115.3mA
-820mV    -81.42mA   -42.31mA   -110.6mA
-500mV    -56.95mA   -35.08mA   -78.57mA
140mV     15.18mA    9.02mA     22.02mA
460mV     44mA       25.98mA    64.37mA
860mV     68.91mA    40.27mA    102.2mA
1.26V     82.21mA    47.42mA    124mA
1.66V     85.53mA    48.99mA    130.3mA
3.18V     89.84mA    53.65mA    132.3mA
3.66V     94.05mA    53.65mA    143.4mA
5V        94.05mA    53.65mA    143.4mA
[Pullup]
|Voltage   I(typ)   I(min)   I(max)
-2.5V     100.4mA    65.58mA    133.3mA
-1.24V    100.4mA    65.58mA    133.3mA
-1V       95.08mA    62.85mA    125.9mA
-760mV    78.59mA    53.37mA    100.6mA
-40mV     3.893mA    2.628mA    5.181mA
360mV     -30.97mA   -20.78mA   -41.56mA
600mV     -47.45mA   -31.77mA   -63.92mA
840mV     -60.71mA   -40.52mA   -82.21mA
1.32V     -78.06mA   -51.54mA   -107.3mA
1.64V     -83.42mA   -54.54mA   -116.1mA
2.12V     -86.16mA   -55.91mA   -121.1mA
4.92V     -91mA      -59mA      -128mA
[GND_clamp]
|Voltage   I(typ)   I(min)   I(max)
-2.5V     -9.641A    -9.693A    -9.352A
-1.18V    -3.114A    -3.874A    -2.614A
-1.12V    -2.301A    -3.23A     -1.656A
-1.06V    -1.489A    -2.587A    -706.2mA
-1V       -685.8mA   -1.945A    -119.3mA
-940mV    -149.8mA   -1.304A    -34.74mA
-880mV    -35.55mA   -672.6mA   -23.08mA
-820mV    -16.2mA    -206.4mA   -17.29mA
-760mV    -10.59mA   -57.56mA   -12.42mA
-700mV    -7.162mA   -18.75mA   -8.254mA
-400mV    -112.4uA   -385.2uA   -53.46uA
2.48V     63.1uA     48.03uA    77.39uA
[POWER_clamp]
|Voltage   I(typ)   I(min)   I(max)
-2.49V    881mA      773.1mA    1.07A
-1.14V    95.25mA    122.7mA    82.82mA
-1.11V    79.9mA     109.7mA    64.14mA
-1.05V    50.87mA    84.26mA    30.57mA
-1.02V    37.63mA    72.04mA    17.17mA
-990mV    25.71mA    60.25mA    7.621mA
-930mV    8.217mA    38.43mA    713.9uA
-900mV    3.624mA    28.77mA    182.8uA
-840mV    490.7uA    13.24mA    11.35uA
-780mV    56.55uA    4.324mA    699nA
-660mV    716.7nA    226uA      9.786nA
0V        0A         19.53nA    0A
[Ramp]
| variable   typ   min   max
dV/dt_r  1.20630/1.90526n   0.99744/3.38883n   1.37748/1.30602n
dV/dt_f  1.24320/1.30464n   0.99725/2.43304n   1.42604/0.85161n
R_load = 50.000000
[Rising Waveform]
R_fixture= 50.000000
V_fixture= 2.500000
V_fixture_min= 2.300000
V_fixture_max= 2.700000
|time   V(typ)   V(min)   V(max)
0s        427.5mV    637.3mV    322.6mV
592.6ps   421.7mV    637.4mV    407.4mV
656.7ps   431.2mV    637.3mV    630.4mV
800.8ps   543.8mV    634.7mV    1.626V
961ps     1.216V     636.1mV    2.404V
1.089ns   1.961V     675mV      2.581V
1.201ns   2.279V     769.6mV    2.637V
1.586ns   2.468V     1.981V     2.68V
1.89ns    2.482V     2.244V     2.689V
7.976ns   2.499V     2.299V     2.699V
[Rising Waveform]
R_fixture= 50.000000
V_fixture= 0.0
V_fixture_min= 0.0
V_fixture_max= 0.0
|time   V(typ)   V(min)   V(max)
0s        -1.587uV   -3.865uV   -7.397uV
1.001ns   -33.33mV   -6.989mV   -44.56mV
1.502ns   577.6uV    -27.16mV   185.8mV
1.902ns   112.8mV    -23.7mV    539.1mV
3.303ns   946mV      207.2mV    1.957V
4.404ns   1.617V     543.1mV    2.191V
5.205ns   1.819V     801.7mV    2.244V
7.608ns   1.971V     1.408V     2.289V
11.31ns   2.006V     1.61V      2.296V
49.85ns   2.01V      1.663V     2.296V
[Falling Waveform]
R_fixture= 50.000000
V_fixture= 2.500000
V_fixture_min= 2.300000
V_fixture_max= 2.700000
|time   V(typ)   V(min)   V(max)
0s        2.499V     2.299V     2.699V
1.201ns   2.511V     2.32V      2.709V
1.401ns   2.51V      2.314V     2.529V
1.802ns   2.47V      2.308V     1.837V
2.603ns   1.776V     2.273V     624.4mV
3.504ns   913.5mV    1.972V     415.4mV
4.004ns   672.6mV    1.76V      383.5mV
6.106ns   489.9mV    939.4mV    337.3mV
9.51ns    441mV      714.8mV    324.8mV
49.85ns   427.5mV    637.3mV    322.6mV
[Falling Waveform]
R_fixture= 50.000000
V_fixture= 0.0
V_fixture_min= 0.0
V_fixture_max= 0.0
|time   V(typ)   V(min)   V(max)
0s        2.01V      1.663V     2.296V
400.4ps   2.012V     1.663V     2.274V
528.5ps   2.015V     1.663V     2.099V
640.6ps   1.934V     1.663V     1.757V
912.9ps   1.39V      1.646V     1.009V
1.153ns   914.6mV    1.391V     452.8mV
1.57ns    283.7mV    805.1mV    32.62mV
2.162ns   15.48mV    255.6mV    2.796mV
2.755ns   3.212mV    30.04mV    1.572mV
7.976ns   -1.587uV   -3.865uV   -7.397uV
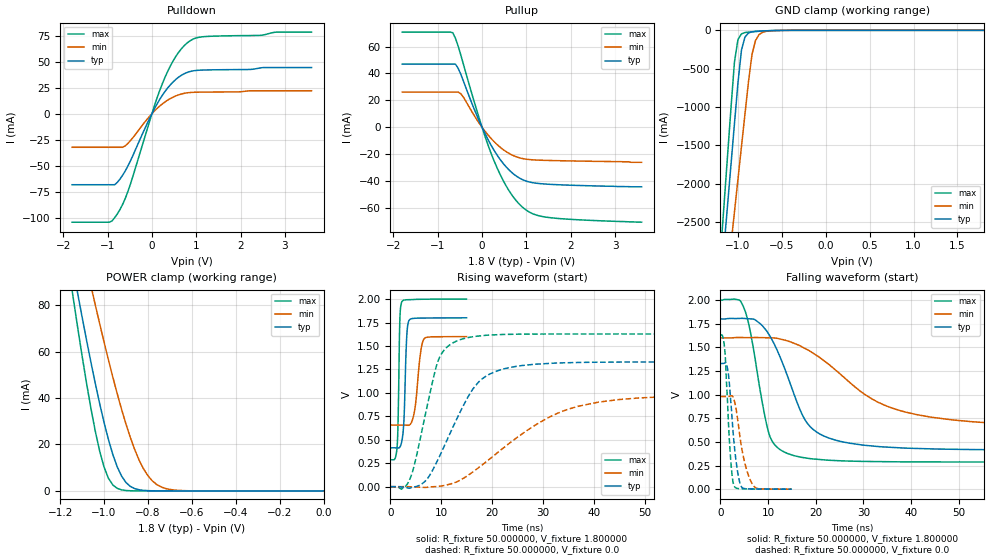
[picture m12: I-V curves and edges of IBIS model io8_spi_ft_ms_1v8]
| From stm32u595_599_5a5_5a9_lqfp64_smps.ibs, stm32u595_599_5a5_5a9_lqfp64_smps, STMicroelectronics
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|   Model io8_spi_ft_ms_1v8
[Model]  io8_spi_ft_ms_1v8
Model_type I/O
Polarity   Non-Inverting
Enable   Active-Low
Vinl =   0.540000V
Vinh =   1.260000V
Vmeas =  0.900000V
Cref =   50.000000pF
Rref =   100.000000M
Vref =   0.0V
C_comp   3.338500pF   3.332300pF   3.378900pF
[Temperature Range]   25.000000   0.140000k   -40.000000
[Pullup Reference]   1.800000V   1.600000V   2.000000V
[Pulldown Reference]   0.0V   0.0V   0.0V
[POWER Clamp Reference]   1.800000V   1.600000V   2.000000V
[GND Clamp Reference]   0.0V   0.0V   0.0V
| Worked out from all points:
|   slope of the pulldown table from 0 to 0.27 V, typ, clamps not added: 13.6 ohm
|   slope of the pullup table from 0 to 0.27 V, typ, clamps not added: 15.9 ohm
|   GND clamp passes 1 mA (typ) near -0.51 V on its own axis
|   POWER clamp passes 1 mA (typ) near -0.86 V on its own axis
|   rising waveform, R_fixture 50.000000, V_fixture 1.800000: 20-80 % time 497ps typ, 1.03ns min, 320ps max; typ from 0.414 V to 1.8 V
|   rising waveform, R_fixture 50.000000, V_fixture 0.0: 20-80 % time 7.39ns typ, 15.7ns min, 4.01ns max; typ from 0 V to 1.33 V
|   falling waveform, R_fixture 50.000000, V_fixture 1.800000: 20-80 % time 6.93ns typ, 16.5ns min, 3.64ns max; typ from 1.8 V to 0.414 V
|   falling waveform, R_fixture 50.000000, V_fixture 0.0: 20-80 % time 1.4ns typ, 2.07ns min, 1.02ns max; typ from 1.33 V to 0 V
[Pulldown]
|Voltage   I(typ)   I(min)   I(max)
-1.8V     -68.38mA   -32.32mA   -104.4mA
-960mV    -68.38mA   -32.32mA   -104.4mA
-780mV    -66.07mA   -32.32mA   -96.42mA
-660mV    -59.2mA    -32.31mA   -87.22mA
-540mV    -50.22mA   -28.51mA   -74.66mA
0V        0A         -300fA     0A
240mV     18.04mA    9.599mA    29.42mA
480mV     30.68mA    16.02mA    50.95mA
780mV     39.47mA    19.98mA    67.56mA
960mV     41.44mA    20.62mA    72.37mA
1.14V     41.99mA    20.78mA    74.01mA
3.6V      44.44mA    22.06mA    78.55mA
[Pullup]
|Voltage   I(typ)   I(min)   I(max)
-1.8V     46.9mA     26.15mA    70.72mA
-660mV    46.9mA     26.15mA    70.21mA
-600mV    46.9mA     26.15mA    66.12mA
-480mV    39.44mA    24.97mA    53.77mA
-60mV     4.42mA     2.808mA    6.308mA
240mV     -15.38mA   -9.6mA     -22.37mA
420mV     -24.43mA   -15.12mA   -35.87mA
600mV     -31.41mA   -19.24mA   -46.67mA
960mV     -39.54mA   -23.52mA   -60.64mA
1.2V      -41.44mA   -24.28mA   -64.94mA
1.56V     -42.42mA   -24.69mA   -67.24mA
3.6V      -44.2mA    -26mA      -70.5mA
[GND_clamp]
|Voltage   I(typ)   I(min)   I(max)
-1.8V     -9.908A    -9.683A    -9.994A
-1.2V     -3.383A    -4.084A    -2.934A
-1.16V    -2.841A    -3.655A    -2.294A
-1.12V    -2.299A    -3.226A    -1.656A
-1.04V    -1.218A    -2.369A    -414.2mA
-1V       -684.7mA   -1.941A    -119.2mA
-960mV    -257.2mA   -1.514A    -45.66mA
-920mV    -87.03mA   -1.089A    -28.93mA
-840mV    -19.35mA   -312.8mA   -18.96mA
-800mV    -13.55mA   -132.4mA   -15.49mA
-720mV    -8.042mA   -25.66mA   -9.49mA
1.8V      0A         13.64nA    0A
[POWER_clamp]
|Voltage   I(typ)   I(min)   I(max)
-1.8V     470.8mA    433.7mA    554.6mA
-1.14V    95.25mA    122.7mA    82.82mA
-1.12V    84.97mA    114mA      70.27mA
-1.06V    55.51mA    88.42mA    35.67mA
-1.04V    46.34mA    80.15mA    25.76mA
-1V       29.51mA    64.13mA    10.3mA
-940mV    10.39mA    41.86mA    1.109mA
-900mV    3.624mA    28.77mA    182.8uA
-840mV    490.7uA    13.24mA    11.35uA
-800mV    116.8uA    6.532mA    1.77uA
-740mV    13.2uA     1.724mA    109.3nA
0V        0A         18.75nA    0A
[Ramp]
| variable   typ   min   max
dV/dt_r  0.79770/7.38029n   0.58799/15.71691n   0.97668/4.00027n
dV/dt_f  0.83161/6.91080n   0.56362/16.49045n   1.02769/3.63712n
R_load = 50.000000
[Rising Waveform]
R_fixture= 50.000000
V_fixture= 1.800000
V_fixture_min= 1.600000
V_fixture_max= 2.000000
|time   V(typ)   V(min)   V(max)
0s        414mV      656.9mV    287.2mV
1.381ns   413mV      656.9mV    456.8mV
1.862ns   420.9mV    656.9mV    1.748V
2.252ns   481.4mV    656.9mV    1.969V
2.703ns   735.9mV    656.7mV    1.989V
3.243ns   1.614V     655.1mV    1.992V
3.664ns   1.771V     655.6mV    1.993V
4.745ns   1.795V     803.4mV    1.996V
6.547ns   1.797V     1.569V     1.998V
14.95ns   1.8V       1.6V       2V
[Rising Waveform]
R_fixture= 50.000000
V_fixture= 0.0
V_fixture_min= 0.0
V_fixture_max= 0.0
|time   V(typ)   V(min)   V(max)
0s        2.122uV    2.366uV    111.2nV
3.604ns   -16.08mV   -99.26uV   52.71mV
6.807ns   56.48mV    -8.505mV   750.8mV
9.409ns   295.3mV    3.688mV    1.345V
14.01ns   830mV      78.63mV    1.572V
17.42ns   1.12V      206.6mV    1.606V
21.42ns   1.242V     379.3mV    1.621V
31.23ns   1.314V     742.1mV    1.628V
40.84ns   1.327V     901.4mV    1.628V
99.7ns    1.33V      980.3mV    1.628V
[Falling Waveform]
R_fixture= 50.000000
V_fixture= 1.800000
V_fixture_min= 1.600000
V_fixture_max= 2.000000
|time   V(typ)   V(min)   V(max)
0s        1.8V       1.6V       2V
4.805ns   1.806V     1.603V     1.932V
6.206ns   1.801V     1.603V     1.684V
10.21ns   1.634V     1.601V     584.3mV
14.21ns   1.177V     1.566V     375mV
18.82ns   662mV      1.459V     323.1mV
27.03ns   486.8mV    1.133V     297.1mV
35.04ns   444.6mV    876.1mV    290.5mV
48.45ns   422.1mV    733.7mV    287.7mV
99.7ns    414mV      656.9mV    287.2mV
[Falling Waveform]
R_fixture= 50.000000
V_fixture= 0.0
V_fixture_min= 0.0
V_fixture_max= 0.0
|time   V(typ)   V(min)   V(max)
0s        1.33V      980.3mV    1.628V
810.8ps   1.333V     980.3mV    1.525V
1.051ns   1.335V     980.3mV    1.377V
1.532ns   1.265V     980.1mV    879.7mV
2.222ns   897.1mV    987.6mV    272.6mV
2.883ns   479.5mV    942.8mV    33.66mV
4.234ns   43.9mV     508.9mV    4.951mV
5.405ns   4.378mV    222.4mV    2.993mV
6.667ns   2.28mV     56.11mV    1.405mV
14.95ns   2.122uV    2.366uV    111.2nV
